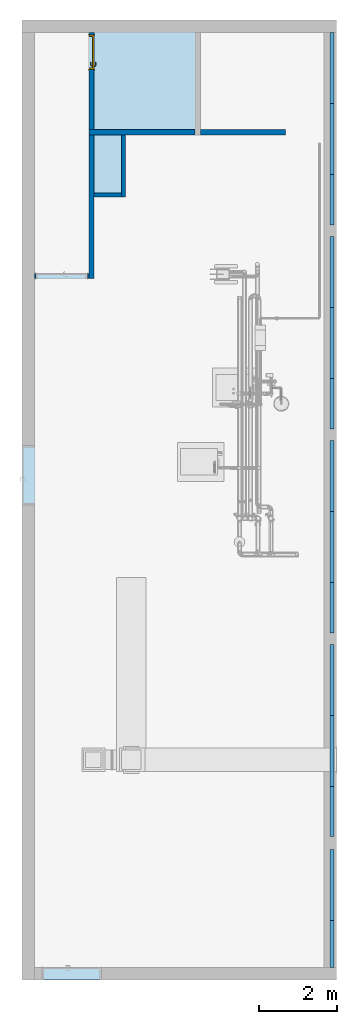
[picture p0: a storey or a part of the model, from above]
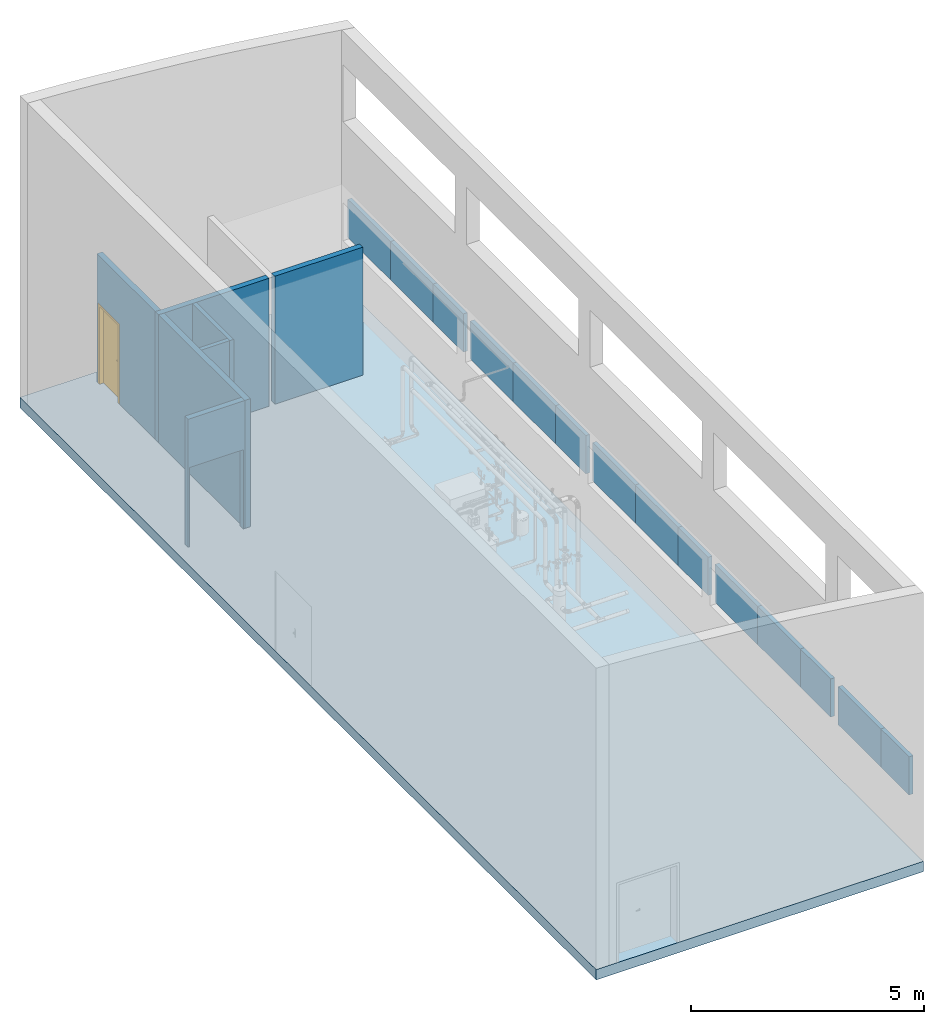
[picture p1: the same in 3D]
Properties of the parts of a building model (IFC2X3), part 1 of 2

# File
Description: ViewDefinition [CoordinationView_V2.0]
File name: 0001
Time: 2023-12-08T14:06:30+01:00
Written by: ODA SDAI 22.12
Made in: 23.0.11.19 - Exporter 23.0.11.19 - Interface utilisateur alternative 23.0.11.19

# IfcProject, 0001
LongName: Nom du projet; Phase: Etat du projet

# IfcSite, Default
RefLatitude: 48, 51, 23, 807373; RefLongitude: 2, 21, 7, 999076; RefElevation: 0 mm

# IfcBuilding
Pset_BuildingCommon - NumberOfStoreys: 3

# IfcBuildingStorey: Niveau:Pointe 8 mm (3)
Name | LongName | Elevation (mm)
Niveau 0 | Niveau 0 | 270
Niveau 1 | Niveau 1 | 3880
Niveau 2 | Niveau 2 | 8105

# IfcBuildingElementProxy: CTA YORK:CTA YORK, CTA YORK:CTA YORK:757549
In: Niveau 0
Type - Material: <Unnamed> (4)
Pset_BuildingElementProxyCommon - Reference: CTA YORK; sets with these values: 2
Pset_ProvisionForVoid - Width: 5000 mm; Height: 750 mm; Depth: 730 mm
Group: Génie climatique Soufflage 1; Génie climatique Air Neuf 1; Génie climatique Reprise 2

# IfcBuildingElementProxy: Chaudière Weishaupt WTC-GB 120-A:Chaudière Weishaupt WTC-GB 120-A (2)
In: Niveau 0
Type - Material: <Unnamed>, Panneau métallique gris foncé, Panneau métallique blanc, logo
Pset_BuildingElementProxyCommon - Reference: Chaudière Weishaupt WTC-GB 120-A; sets with these values: 2
Name (Chaudière Weishaupt WTC-GB 120-A:Chaudière Weishaupt WTC-GB 120-A:...) | Group
1231440 | Chauffage retour 4; Chauffage retour primaire 2; Chauffage aller primaire 4; gaz naturel 5
1236392 | Chauffage retour primaire 2; Chauffage aller primaire 4

# IfcBuildingElementProxy: Clapet coupe-feu - Rectangulaire - Simple:Standard (2)
In: Niveau 1
Type - Material: <Unnamed>
Pset_BuildingElementProxyCommon - Reference: Standard; sets with these values: 2
Pset_ProvisionForVoid - Width: 150 mm; Height: 424 mm; Depth: 424 mm
Name (Clapet coupe-feu - Rectangulaire - Simple:Standard:...) | Group
756469 | Génie climatique Soufflage 1
758548 | Génie climatique Reprise 2

# IfcBuildingElementProxy: Ecran clavier souris PC:Ecran clavier souris PC (21)
In: Niveau 1
Type - Material: Plastique - Blanc brillant (122), <Unnamed>, Verre - Noir brillant
Pset_BuildingElementProxyCommon - Reference: Ecran clavier souris PC; sets with these values: 2
Name (Ecran clavier souris PC:Ecran clavier souris PC:...) | Material
1175628
1175630 | Plastique - Blanc brillant, <Unnamed>, Verre - Noir brillant
1175632 | Plastique - Blanc brillant, <Unnamed>, Verre - Noir brillant
1175634 | Plastique - Blanc brillant, <Unnamed>, Verre - Noir brillant
1175636 | Plastique - Blanc brillant, <Unnamed>, Verre - Noir brillant
1175638 | Plastique - Blanc brillant, <Unnamed>, Verre - Noir brillant
1175640 | Plastique - Blanc brillant, <Unnamed>, Verre - Noir brillant
1175642 | Plastique - Blanc brillant, <Unnamed>, Verre - Noir brillant
1175654 | Plastique - Blanc brillant, <Unnamed>, Verre - Noir brillant
1175657 | Plastique - Blanc brillant, <Unnamed>, Verre - Noir brillant
1175659 | Plastique - Blanc brillant, <Unnamed>, Verre - Noir brillant
1175664 | Plastique - Blanc brillant, <Unnamed>, Verre - Noir brillant
1175665 | Plastique - Blanc brillant, <Unnamed>, Verre - Noir brillant
1175669 | Plastique - Blanc brillant, <Unnamed>, Verre - Noir brillant
1175670 | Plastique - Blanc brillant, <Unnamed>, Verre - Noir brillant
1175674 | Plastique - Blanc brillant, <Unnamed>, Verre - Noir brillant
1175675 | Plastique - Blanc brillant, <Unnamed>, Verre - Noir brillant
1175679 | Plastique - Blanc brillant, <Unnamed>, Verre - Noir brillant
1175680 | Plastique - Blanc brillant, <Unnamed>, Verre - Noir brillant
1175684 | Plastique - Blanc brillant, <Unnamed>, Verre - Noir brillant
1175685 | Plastique - Blanc brillant, <Unnamed>, Verre - Noir brillant

# IfcBuildingElementProxy: HC_Expansion Vessel_MEPcontent_Flamco_26105 Contraflex100 25-6:vase d'expansion gitral, HC_Expansion Vessel_MEPcontent_Flamco_26105 Contraflex100 25-6:vase d'expansion gitral:1371709
In: Niveau 0
Type - Material: Color RGB 204-0-0
Type - Pset_ManufacturerTypeInformation - Manufacturer: Flamco
Pset_BuildingElementProxyCommon - Reference: vase d'expansion gitral; sets with these values: 2

# IfcBuildingElementProxy: Imprimante - Table:Imprimante - Table, Imprimante - Table:Imprimante - Table:1175661
In: Niveau 1
Type - Material: Plastique - Blanc cassé (5)
Pset_BuildingElementProxyCommon - Reference: Imprimante - Table; sets with these values: 2

# IfcBuildingElementProxy: M_Heat Exchanger_Plate_MEPcontent_CHAROT_Solo_L_FR-FR:THIS IS A TYPE CATALOG FAMILY, M_Heat Exchanger_Plate_MEPcontent_CHAROT_Solo_L_FR-FR:THIS IS A TYPE CATALOG FAMILY:1247341
In: Niveau 0
Type - Material: Color RGB 226-110-014, Color RGB 191-191-191, Color RGB 103-103-103, Color RGB 252-188-132
Type - Pset_ManufacturerTypeInformation - Manufacturer: CHAROT
Type - Pset_ProvisionForVoid - Width: 506 mm; Height: 995 mm; Diameter: 63.5 mm; Depth: 710 mm
Material: Color RGB 191-191-191, Color RGB 252-188-132, Color RGB 226-110-014, Color RGB 103-103-103; Group: Chauffage retour 3
Pset_BuildingElementProxyCommon - Reference: THIS IS A TYPE CATALOG FAMILY; sets with these values: 2
Pset_ProvisionForVoid - Width: 0.154229 mm

# IfcBuildingElementProxy: M_Meter_Gas_MEPcontent_Unspecified:G2.5, M_Meter_Gas_MEPcontent_Unspecified:G2.5:1422788
In: Niveau 0
Type - Material: Color RGB 255-255-0 (2), Color RGB 127-127-127 (2), Color RGB 255-255-255 (2)
Type - Pset_ManufacturerTypeInformation - Manufacturer: Unspecified
Type - Pset_ProvisionForVoid - Width: 133 mm
Pset_BuildingElementProxyCommon - Reference: G2.5; sets with these values: 2
Pset_ProvisionForVoid - Width: 0.0405384 mm
Group: gaz naturel 5

# IfcBuildingElementProxy: Male:Male (221)
In: Niveau 0
Type - Material: Copper Conex
Pset_BuildingElementProxyCommon - Reference: Male; sets with these values: 2
Name (Male:Male:...)
1362084
1362085
1362086
1362087
1362088
1362089
1362090
1362091
1362092
1362093
1362094
1362095
1362096
1362097
1362098
1362099
1362100
1362101
1362102
1362103
1362104
1362105
1362106
1362107
1362711
1362712
1362713
1362714
1362715
1362716
1362717
1362718
1362719
1362720
1362721
1362722
1362723
1362724
1362725
1362726
1362727
1362728
1362729
1362730
1362731
1362732
1362733
1362734
1362820
1362821
1362822
1362823
1362824
1362825
1362826
1362827
1362828
1362829
1362830
1362831
1362832
1362833
1362834
1362835
1362836
1362837
1362838
1362839
1362840
1362841
1362842
1362843
1363901
1363902
1363903
1363904
1363905
1363906
1363907
1363908
1363909
1363910
1363911
1363912
1363913
1363914
1363915
1363916
1363917
1363918
1363919
1363920
1363921
1363922
1363923
1363924
1364621
1364622
1364623
1364624
1364625
1364626
1364627
1364628
1364629
1364630
1364631
1364632
1364633
1364634
1364635
1364636
1364637
1364638
1364639
1364640
1364641
1364642
1364643
1364644
1364876
1364877
1364878
1364879
1364880
1364881
1364882
1364883
1364884
1364885
1364886
1364887
1364888
1364889
1364890
1364891
1364892
1364893
1364894
1364895
1364896
1364897
1364898
1364899
1364900
1364901
1364902
1364903
1364974
1364975
1364976
1364977
1364978
1364979
1364980
1364981
1364982
1364983
1364984
1364985
1364986
1364987
1364988
1364989
1364990
1364991
1364992
1364993
1364994
1364995
1364996
1364997
1364998
1364999
1365000
1365001
1365287
1365288
1365289
1365290
1365291
1365292
1365293
1365294
1365295
1365296
1365297
1365298
1365299
1365300
1365301
1365302
1365303
1365304
1365305
1365306
1365307
1365308
1365309
1365310
1365311
1365312
1365313
1365314
1383095
1383096
1383097
1383098
1383099
1383100
1383101
1383215
1383372
1400765
1400766
1400767
1400768
1400769
1400770
1400771
1400772

# IfcBuildingElementProxy: Plumbing_Other_IVAR_DirtstopXL_Swiveling-Magnetic-Dirt-Separator-With-Strainer:- Pot à boues Flamco-Clean Smart 1''1/4 33 x 42 Ecoplus, Plumbing_Other_IVAR_DirtstopXL_Swiveling-Magnetic-Dirt-Separator-With-Strainer:- Pot à boues Flamco-Clean Smart 1''1/4 33 x 42 Ecoplus:1433220
In: Niveau 0
Type - Material: <Unnamed> (2), BRASS - CW617N (9), Techno-Polymer RAL7016 (12), Techno-Polymer BLACK (4), PA Nylon 6 - White, Brass - Nickel, EPDM - Black (2)
Type - Pset_ManufacturerTypeInformation - Manufacturer: IVAR
Pset_BuildingElementProxyCommon - Reference: - Pot à boues Flamco-Clean Smart 1''1/4 33 x 42 Ecoplus; sets with these values: 2

# IfcBuildingElementProxy: Poste de travail PC:Poste de travail PC (21)
In: Niveau 1
Type - Material: Plastique - Noir satiné, Métal - Aluminium satiné
Pset_BuildingElementProxyCommon - Reference: Poste de travail PC; sets with these values: 2
Name (Poste de travail PC:Poste de travail PC:...)
1175627
1175629
1175631
1175633
1175635
1175637
1175639
1175641
1175653
1175656
1175658
1175663
1175666
1175668
1175671
1175673
1175676
1175678
1175681
1175683
1175686

# IfcBuildingElementProxy: Pump-Inline_Circulator-Grundfos_MAGNA3D-EMCS V3-0:MAGNA 32-100 180, Pump-Inline_Circulator-Grundfos_MAGNA3D-EMCS V3-0:MAGNA 32-100 180:1353054
In: Niveau 0
Type - Material: Grundfos - Light Black (7), Grundfos - Red (2), Grundfos - Insulation
Type - Pset_ManufacturerTypeInformation - Manufacturer: Grundfos
Pset_BuildingElementProxyCommon - Reference: MAGNA 32-100 180; sets with these values: 2
Group: Chauffage retour primaire 1

# IfcBuildingElementProxy: Pump-Inline_Circulator-Grundfos_UUPS100:PLEASE USE TYPE CATALOG, Pump-Inline_Circulator-Grundfos_UUPS100:PLEASE USE TYPE CATALOG:1298291
In: Niveau 0
Type - Material: Grundfos - Light Black (2), Grundfos - Red (9)
Type - Pset_ManufacturerTypeInformation - Manufacturer: Grundfos
Pset_BuildingElementProxyCommon - Reference: PLEASE USE TYPE CATALOG; sets with these values: 2
Group: Chauffage aller 5

# IfcBuildingElementProxy: Socle chaudière 1000x1200x200:Socle chaudière 1000x1200x200 (2)
In: Niveau 0
Type - Material: Acier noir, Acier rouge
Pset_BuildingElementProxyCommon - Reference: Socle chaudière 1000x1200x200; sets with these values: 2
Name (Socle chaudière 1000x1200x200:Socle chaudière 1000x1200x200:...)
1224524
1236048

# IfcBuildingElementProxy: Vidéoprojecteur fixé au plafond:Vidéoprojecteur fixé au plafond, Vidéoprojecteur fixé au plafond:Vidéoprojecteur fixé au plafond:981224
In: Niveau 1
Type - Material: Plastique - Noir satiné
Material: Plastique - Noir satiné, Plastique - Blanc brillant, <Unnamed>, Verre - Objectif
Pset_BuildingElementProxyCommon - Reference: Vidéoprojecteur fixé au plafond; sets with these values: 2

# IfcBuildingElementProxy: détendeur gaz:détendeur gaz, détendeur gaz:détendeur gaz:1431917
In: Niveau 0
Type - Material: Par défaut (5)
Type - Pset_ManufacturerTypeInformation - Manufacturer: Mesura
Pset_BuildingElementProxyCommon - Reference: détendeur gaz; sets with these values: 2
Pset_ProvisionForVoid - Depth: 120 mm

# IfcCovering: Plafond composé:Quadrillage 600 x 600 mm (7)
Type - PredefinedType: CEILING
Type - Pset_CoveringCommon - TotalThickness: 52 mm
Material: Par défaut 36 mm, Panneau de plafond 600 x 600 16 mm
Pset_CoveringCommon - Reference: Quadrillage 600 x 600 mm; Finish: Panneau de plafond 600 x 600;
Pset_QuantityTakeOff - Reference: Quadrillage 600 x 600 mm
Name (Plafond composé:Quadrillage 600 x 600 mm:...) | In
737611 | Niveau 0
737628 | Niveau 0
737641 | Niveau 1
737655 | Niveau 1
737665 | Niveau 1
737673 | Niveau 1
737682 | Niveau 1

# IfcCurtainWall: Mur-rideau:Vitrage extérieur (10)
Type - Pset_CurtainWallCommon - IsExternal: yes
Pset_CurtainWallCommon - Reference: Vitrage extérieur
Pset_QuantityTakeOff - Reference: Vitrage extérieur
Name (Mur-rideau:Vitrage extérieur:...) | In
739993 | Niveau 0
740630 | Niveau 0
740654 | Niveau 0
740678 | Niveau 0
740854 | Niveau 0
741319 | Niveau 1
741387 | Niveau 1
741411 | Niveau 1
741435 | Niveau 1
741660 | Niveau 1

# IfcDistributionPort (717)
Description: Flow
Name | FlowDirection | Group
InPort_750789 | SINK | Génie climatique Soufflage 1
OutPort_755056 | SOURCE | Génie climatique Soufflage 1
InPort_750978 | SINK | Génie climatique Soufflage 1
OutPort_750789 | SOURCE | Génie climatique Soufflage 1
InPort_750800 | SINK | Génie climatique Soufflage 1
2 x OutPort_750978 | SOURCE | Génie climatique Soufflage 1
InPort_750837 | SINK | Génie climatique Soufflage 1
OutPort_750800 | SOURCE | Génie climatique Soufflage 1
InPort_750882 | SINK | Génie climatique Soufflage 1
2 x OutPort_750817 | SOURCE | Génie climatique Soufflage 1
InPort_752768 | SINK | Génie climatique Soufflage 1
InPort_750817 | SINK | Génie climatique Soufflage 1
OutPort_750837 | SOURCE | Génie climatique Soufflage 1
InPort_752774 | SINK | Génie climatique Soufflage 1
2 x OutPort_750841 | SOURCE | Génie climatique Soufflage 1
InPort_750918 | SINK | Génie climatique Soufflage 1
InPort_750841 | SINK | Génie climatique Soufflage 1
OutPort_750882 | SOURCE | Génie climatique Soufflage 1
InPort_752785 | SINK | Génie climatique Soufflage 1
2 x OutPort_750885 | SOURCE | Génie climatique Soufflage 1
InPort_750949 | SINK | Génie climatique Soufflage 1
InPort_750885 | SINK | Génie climatique Soufflage 1
OutPort_750918 | SOURCE | Génie climatique Soufflage 1
InPort_750921 | SINK | Génie climatique Soufflage 1
OutPort_750949 | SOURCE | Génie climatique Soufflage 1
InPort_750958 | SINK | Génie climatique Soufflage 1
OutPort_750921 | SOURCE | Génie climatique Soufflage 1
InPort_750952 | SINK | Génie climatique Soufflage 1
OutPort_750958 | SOURCE | Génie climatique Soufflage 1
InPort_752788 | SINK | Génie climatique Soufflage 1
OutPort_750952 | SOURCE | Génie climatique Soufflage 1
InPort_753398 | SINK | Génie climatique Soufflage 1
InPort_752171 | SINK | Génie climatique Soufflage 1
OutPort_752765 | SOURCE | Génie climatique Soufflage 1
InPort_752287 | SINK | Génie climatique Soufflage 1
OutPort_752771 | SOURCE | Génie climatique Soufflage 1
InPort_752402 | SINK | Génie climatique Soufflage 1
OutPort_752782 | SOURCE | Génie climatique Soufflage 1
InPort_752454 | SINK | Génie climatique Soufflage 1
OutPort_752788 | SOURCE | Génie climatique Soufflage 1
InPort_752765 | SINK | Génie climatique Soufflage 1
OutPort_752768 | SOURCE | Génie climatique Soufflage 1
InPort_752771 | SINK | Génie climatique Soufflage 1
OutPort_752774 | SOURCE | Génie climatique Soufflage 1
InPort_752782 | SINK | Génie climatique Soufflage 1
OutPort_752785 | SOURCE | Génie climatique Soufflage 1
InPort_753417 | SINK | Génie climatique Soufflage 1
OutPort_753398 | SOURCE | Génie climatique Soufflage 1
InPort_753420 | SINK | Génie climatique Soufflage 1
OutPort_753417 | SOURCE | Génie climatique Soufflage 1
InPort_753441 | SINK | Génie climatique Soufflage 1
3 x OutPort_753420 | SOURCE | Génie climatique Soufflage 1
InPort_754116 | SINK | Génie climatique Soufflage 1
InPort_754103 | SINK | Génie climatique Soufflage 1
InPort_753433 | SINK | Génie climatique Soufflage 1
2 x OutPort_753475 | SOURCE | Génie climatique Soufflage 1
InPort_753454 | SINK | Génie climatique Soufflage 1
OutPort_753433 | SOURCE | Génie climatique Soufflage 1
InPort_753476 | SINK | Génie climatique Soufflage 1
OutPort_753441 | SOURCE | Génie climatique Soufflage 1
InPort_753444 | SINK | Génie climatique Soufflage 1
OutPort_753454 | SOURCE | Génie climatique Soufflage 1
InPort_754094 | SINK | Génie climatique Soufflage 1
OutPort_753444 | SOURCE | Génie climatique Soufflage 1
InPort_753481 | SINK | Génie climatique Soufflage 1
InPort_753475 | SINK | Génie climatique Soufflage 1
2 x OutPort_753476 | SOURCE | Génie climatique Soufflage 1
InPort_754090 | SINK | Génie climatique Soufflage 1
InPort_754097 | SINK | Génie climatique Soufflage 1
OutPort_753481 | SOURCE | Génie climatique Soufflage 1
InPort_753735 | SINK | Génie climatique Soufflage 1
OutPort_754113 | SOURCE | Génie climatique Soufflage 1
InPort_753793 | SINK | Génie climatique Soufflage 1
OutPort_754100 | SOURCE | Génie climatique Soufflage 1
InPort_753835 | SINK | Génie climatique Soufflage 1
OutPort_754087 | SOURCE | Génie climatique Soufflage 1
InPort_753912 | SINK | Génie climatique Soufflage 1
OutPort_754097 | SOURCE | Génie climatique Soufflage 1
InPort_753971 | SINK | Génie climatique Soufflage 1
OutPort_754094 | SOURCE | Génie climatique Soufflage 1
InPort_754087 | SINK | Génie climatique Soufflage 1
OutPort_754090 | SOURCE | Génie climatique Soufflage 1
InPort_754100 | SINK | Génie climatique Soufflage 1
OutPort_754103 | SOURCE | Génie climatique Soufflage 1
InPort_754113 | SINK | Génie climatique Soufflage 1
OutPort_754116 | SOURCE | Génie climatique Soufflage 1
InPort_755056 | SINK | Génie climatique Soufflage 1
OutPort_755057 | SOURCE | Génie climatique Soufflage 1
InPort_755057 | SINK | Génie climatique Soufflage 1
OutPort_755218 | SOURCE | Génie climatique Soufflage 1
InPort_755218 | SINK | Génie climatique Soufflage 1
OutPort_756472 | SOURCE | Génie climatique Soufflage 1
InPort_756469 | SINK | Génie climatique Soufflage 1
OutPort_755245 | SOURCE | Génie climatique Soufflage 1
InPort_755245 | SINK | Génie climatique Soufflage 1
OutPort_755273 | SOURCE | Génie climatique Soufflage 1
InPort_755273 | SINK | Génie climatique Soufflage 1
OutPort_755256 | SOURCE | Génie climatique Soufflage 1
InPort_755256 | SINK | Génie climatique Soufflage 1
OutPort_757967 | SOURCE | Génie climatique Soufflage 1
InPort_757967 | SINK | Génie climatique Soufflage 1
OutPort_755277 | SOURCE | Génie climatique Soufflage 1
InPort_755277 | SINK | Génie climatique Soufflage 1
OutPort_757968 | SOURCE | Génie climatique Soufflage 1
InPort_756472 | SINK | Génie climatique Soufflage 1
OutPort_756469 | SOURCE | Génie climatique Soufflage 1
InPort_757968 | SINK | Génie climatique Soufflage 1
OutPort_757549 | SOURCE | Génie climatique Soufflage 1
InPort_757549 | SINK | Génie climatique Air Neuf 1
OutPort_763756 | SOURCE | Génie climatique Air Neuf 1
InPort_757549 | SINK | Génie climatique Reprise 2
OutPort_758402 | SOURCE | Génie climatique Reprise 2
InPort_758050 | SINK | Génie climatique Reprise 2
OutPort_758134 | SOURCE | Génie climatique Reprise 2
InPort_758504 | SINK | Génie climatique Reprise 2
OutPort_758050 | SOURCE | Génie climatique Reprise 2
InPort_758130 | SINK | Génie climatique Reprise 2
OutPort_758548 | SOURCE | Génie climatique Reprise 2
InPort_758134 | SINK | Génie climatique Reprise 2
OutPort_758130 | SOURCE | Génie climatique Reprise 2
InPort_758402 | SINK | Génie climatique Reprise 2
OutPort_758431 | SOURCE | Génie climatique Reprise 2
InPort_758431 | SINK | Génie climatique Reprise 2
OutPort_758424 | SOURCE | Génie climatique Reprise 2
InPort_758424 | SINK | Génie climatique Reprise 2
OutPort_758506 | SOURCE | Génie climatique Reprise 2
InPort_758483 | SINK | Génie climatique Reprise 2
OutPort_758504 | SOURCE | Génie climatique Reprise 2
InPort_758506 | SINK | Génie climatique Reprise 2
OutPort_758483 | SOURCE | Génie climatique Reprise 2
Port_758548 | SINK | Génie climatique Reprise 2
Port_762252 | SOURCE
Port_762397 | SOURCE
InPort_763721 | SINK | Génie climatique Air Neuf 1
OutPort_763887 | SOURCE | Génie climatique Air Neuf 1
InPort_764588 | SINK | Génie climatique Air Neuf 1
OutPort_763721 | SOURCE | Génie climatique Air Neuf 1
InPort_763756 | SINK | Génie climatique Air Neuf 1
OutPort_764589 | SOURCE | Génie climatique Air Neuf 1
InPort_764589 | SINK | Génie climatique Air Neuf 1
OutPort_764588 | SOURCE | Génie climatique Air Neuf 1
2 x InPort_1226026 | SOURCEANDSINK | Chauffage aller 1
OutPort_1226088 | SOURCEANDSINK | Chauffage aller 1
OutPort_1226085 | SOURCEANDSINK | Chauffage aller 1
InPort_1226918 | SOURCEANDSINK | Chauffage retour 3
2 x OutPort_1227515 | SOURCEANDSINK | Chauffage retour 3
2 x InPort_1227406 | SOURCEANDSINK | Chauffage retour 3
2 x OutPort_1227514 | SOURCEANDSINK | Chauffage retour 3
OutPort_1229989 | SOURCEANDSINK | Chauffage retour 3
2 x InPort_1227422 | SOURCEANDSINK | Chauffage retour 3
OutPort_1230780 | SOURCEANDSINK | Chauffage retour 3
InPort_1227514 | SOURCEANDSINK | Chauffage retour 3
2 x InPort_1228611 | SOURCEANDSINK | Chauffage aller 3
2 x OutPort_1231071 | SOURCEANDSINK | Chauffage aller 3
2 x OutPort_1231069 | SOURCEANDSINK | Chauffage aller 3
3 x InPort_1228619 | SOURCEANDSINK | Chauffage aller 3
2 x OutPort_1247731 | SOURCEANDSINK | Chauffage aller 3
2 x OutPort_1301528 | SOURCEANDSINK | Chauffage aller 3
InPort_1229948 | SOURCEANDSINK | Chauffage aller 4
OutPort_1229989 | SOURCEANDSINK | Chauffage aller 4
Port_1229948 | SOURCEANDSINK | Chauffage aller 4
2 x InPort_1230697 | SOURCEANDSINK | Chauffage aller 3
2 x OutPort_1231029 | SOURCEANDSINK | Chauffage aller 3
OutPort_1276218 | SOURCEANDSINK | Chauffage aller 3
InPort_1230780 | SOURCEANDSINK | Chauffage retour 3
OutPort_1276214 | SOURCEANDSINK | Chauffage retour 3
2 x InPort_1231015 | SOURCEANDSINK | Chauffage aller 3
InPort_1231440 | SOURCEANDSINK | Chauffage retour 4
2 x OutPort_1251086 | SOURCEANDSINK | Chauffage retour 4
InPort_1231440 | SOURCEANDSINK | Chauffage retour primaire 2
OutPort_1318675 | SOURCEANDSINK | Chauffage retour primaire 2
Port_1231440 | SINK
InPort_1231440 | SOURCEANDSINK | Chauffage aller primaire 4
OutPort_1319182 | SOURCEANDSINK | Chauffage aller primaire 4
Port_1231440 | SOURCE
InPort_1231440 | SINK | gaz naturel 5
OutPort_1422933 | SOURCE | gaz naturel 5
2 x InPort_1232776 | SOURCEANDSINK | Chauffage aller 3
2 x OutPort_1247733 | SOURCEANDSINK | Chauffage aller 3
InPort_1232794 | SOURCEANDSINK | Chauffage aller 5
OutPort_1233212 | SOURCEANDSINK | Chauffage aller 5
Port_1232794 | SOURCEANDSINK | Chauffage aller 5
2 x InPort_1232892 | SOURCEANDSINK | Chauffage aller 5
OutPort_1233118 | SOURCEANDSINK | Chauffage aller 5
2 x OutPort_1233286 | SOURCEANDSINK | Chauffage aller 5
InPort_1233212 | SOURCEANDSINK | Chauffage aller 5
2 x OutPort_1233287 | SOURCEANDSINK | Chauffage aller 5
2 x InPort_1233215 | SOURCEANDSINK | Chauffage aller 5
OutPort_1233302 | SOURCEANDSINK | Chauffage aller 5
InPort_1233286 | SOURCEANDSINK | Chauffage aller 5
2 x InPort_1233291 | SOURCEANDSINK | Chauffage aller 5
2 x OutPort_1298984 | SOURCEANDSINK | Chauffage aller 5
2 x OutPort_1301420 | SOURCEANDSINK | Chauffage aller 5
InPort_1233302 | SOURCEANDSINK | Chauffage aller 5
OutPort_1276068 | SOURCEANDSINK | Chauffage aller 5
2 x InPort_1233352 | SOURCEANDSINK | Chauffage aller 5
2 x OutPort_1301418 | SOURCEANDSINK | Chauffage aller 5
3 x InPort_1233375 | SOURCEANDSINK | Chauffage aller 5
2 x OutPort_1300699 | SOURCEANDSINK | Chauffage aller 5
2 x OutPort_1233546 | SOURCEANDSINK | Chauffage aller 5
2 x InPort_1233538 | SOURCEANDSINK | Chauffage aller 5
2 x OutPort_1247588 | SOURCEANDSINK | Chauffage aller 5
Port_1233709 | SOURCEANDSINK | Chauffage retour primaire 2
InPort_1233709 | SOURCEANDSINK | Chauffage retour primaire 2
2 x OutPort_1233780 | SOURCEANDSINK | Chauffage retour primaire 2
2 x InPort_1233772 | SOURCEANDSINK | Chauffage retour primaire 2
OutPort_1234849 | SOURCEANDSINK | Chauffage retour primaire 2
2 x InPort_1233937 | SOURCEANDSINK | Chauffage retour primaire 2
OutPort_1276390 | SOURCEANDSINK | Chauffage retour primaire 2
OutPort_1234851 | SOURCEANDSINK | Chauffage retour primaire 2
InPort_1234127 | SOURCEANDSINK | Chauffage aller 2
2 x OutPort_1300229 | SOURCEANDSINK | Chauffage aller 2
2 x InPort_1234127 | SOURCEANDSINK | Chauffage retour primaire 1
2 x OutPort_1235545 | SOURCEANDSINK | Chauffage retour primaire 1
OutPort_1234851 | SOURCEANDSINK | Chauffage retour primaire 1
2 x InPort_1234299 | SOURCEANDSINK | Chauffage retour primaire 1
2 x OutPort_1235543 | SOURCEANDSINK | Chauffage retour primaire 1
2 x InPort_1234299 | SOURCEANDSINK | Chauffage retour primaire 2
2 x OutPort_1238957 | SOURCEANDSINK | Chauffage retour primaire 2
OutPort_1234350 | SOURCEANDSINK | Chauffage retour primaire 2
2 x OutPort_1238229 | SOURCEANDSINK | Chauffage retour primaire 1
InPort_1234849 | SOURCEANDSINK | Chauffage retour primaire 2
OutPort_1276386 | SOURCEANDSINK | Chauffage retour primaire 2
2 x InPort_1235533 | SOURCEANDSINK | Chauffage retour primaire 1
InPort_1235629 | SOURCEANDSINK | Chauffage aller primaire 4
2 x OutPort_1262224 | SOURCEANDSINK | Chauffage aller primaire 4
Port_1235629 | SOURCEANDSINK | Chauffage aller primaire 4
2 x InPort_1235760 | SOURCEANDSINK | Chauffage aller primaire 4
2 x OutPort_1262222 | SOURCEANDSINK | Chauffage aller primaire 4
3 x InPort_1235770 | SOURCEANDSINK | Chauffage aller primaire 4
2 x OutPort_1300048 | SOURCEANDSINK | Chauffage aller primaire 4
2 x OutPort_1239954 | SOURCEANDSINK | Chauffage aller primaire 4
Port_1235770 | SOURCEANDSINK | Chauffage aller primaire 4
Port_1235854 | SOURCEANDSINK | Chauffage aller primaire 1
InPort_1236392 | SOURCEANDSINK | Chauffage aller primaire 4
OutPort_1238980 | SOURCEANDSINK | Chauffage aller primaire 4
2 x Port_1236392 | SINK
InPort_1236392 | SOURCEANDSINK | Chauffage retour primaire 2
OutPort_1238888 | SOURCEANDSINK | Chauffage retour primaire 2
2 x Port_1236392 | SOURCE
2 x Port_1237930 | SOURCEANDSINK | Chauffage aller 6
2 x InPort_1237938 | SOURCEANDSINK | Chauffage retour primaire 1
2 x OutPort_1238240 | SOURCEANDSINK | Chauffage retour primaire 1
2 x InPort_1238232 | SOURCEANDSINK | Chauffage retour primaire 1
OutPort_1238373 | SOURCEANDSINK | Chauffage retour primaire 1
2 x InPort_1238361 | SOURCEANDSINK | Chauffage retour primaire 1
2 x OutPort_1318694 | SOURCEANDSINK | Chauffage retour primaire 1
OutPort_1310541 | SOURCEANDSINK | Chauffage retour primaire 1
InPort_1238373 | SOURCEANDSINK | Chauffage retour primaire 1
OutPort_1366838 | SOURCEANDSINK | Chauffage retour primaire 1
2 x InPort_1238876 | SOURCEANDSINK | Chauffage retour primaire 2
2 x OutPort_1238960 | SOURCEANDSINK | Chauffage retour primaire 2
2 x OutPort_1238890 | SOURCEANDSINK | Chauffage retour primaire 2
InPort_1238888 | SOURCEANDSINK | Chauffage retour primaire 2
2 x InPort_1238893 | SOURCEANDSINK | Chauffage retour primaire 2
InPort_1238980 | SOURCEANDSINK | Chauffage aller primaire 4
2 x OutPort_1239957 | SOURCEANDSINK | Chauffage aller primaire 4
2 x InPort_1238994 | SOURCEANDSINK | Chauffage aller primaire 4
Port_1240949 | SOURCE
2 x Port_1241064 | SOURCEANDSINK | Chauffage aller primaire 3
2 x Port_1247341 | SOURCE
InPort_1247341 | SOURCEANDSINK | Chauffage retour 3
OutPort_1247673 | SOURCEANDSINK | Chauffage retour 3
Port_1247341 | SINK
InPort_1247532 | SOURCEANDSINK | Chauffage retour 2
OutPort_1247586 | SOURCEANDSINK | Chauffage retour 2
Port_1247532 | SOURCEANDSINK | Chauffage retour 2
InPort_1247586 | SOURCEANDSINK | Chauffage aller 5
2 x InPort_1247649 | SOURCEANDSINK | Chauffage aller 3
OutPort_1247673 | SOURCEANDSINK | Chauffage aller 3
OutPort_1247724 | SOURCEANDSINK | Chauffage aller 3
2 x InPort_1247722 | SOURCEANDSINK | Chauffage aller 3
2 x OutPort_1247726 | SOURCEANDSINK | Chauffage aller 3
InPort_1247724 | SOURCEANDSINK | Chauffage aller 3
Port_1247777 | SOURCEANDSINK | Chauffage retour 1
InPort_1247777 | SOURCEANDSINK | Chauffage retour 1
2 x OutPort_1248059 | SOURCEANDSINK | Chauffage retour 1
4 x InPort_1247800 | SOURCEANDSINK | Chauffage retour 1
2 x OutPort_1248134 | SOURCEANDSINK | Chauffage retour 1
2 x OutPort_1248155 | SOURCEANDSINK | Chauffage retour 1
2 x OutPort_1248173 | SOURCEANDSINK | Chauffage retour 1
InPort_1248126 | SOURCEANDSINK | Chauffage retour 1
Port_1248126 | SOURCEANDSINK | Chauffage retour 1
InPort_1248144 | SOURCEANDSINK | Chauffage retour 1
Port_1248144 | SOURCEANDSINK | Chauffage retour 1
InPort_1248165 | SOURCEANDSINK | Chauffage retour 1
Port_1248165 | SOURCEANDSINK | Chauffage retour 1
Port_1248396 | SOURCE
Port_1248396 | SINK
Port_1249217 | SOURCE
Port_1250934 | SINK
Port_1251073 | SOURCEANDSINK | Chauffage retour 4
InPort_1251073 | SOURCEANDSINK | Chauffage retour 4
2 x InPort_1251114 | SOURCEANDSINK | Chauffage retour 5
2 x OutPort_1251134 | SOURCEANDSINK | Chauffage retour 5
2 x OutPort_1251160 | SOURCEANDSINK | Chauffage retour 5
InPort_1251122 | SOURCEANDSINK | Chauffage retour 5
Port_1251122 | SOURCEANDSINK | Chauffage retour 5
InPort_1251152 | SOURCEANDSINK | Chauffage retour 5
Port_1251152 | SOURCEANDSINK | Chauffage retour 5
2 x Port_1251172 | SOURCEANDSINK | Chauffage retour 5
Port_1251988 | SINK
2 x Port_1252877 | SOURCEANDSINK
Port_1253088 | SOURCE
Port_1253587 | SINK
Port_1253587 | SOURCE
Port_1272783 | SOURCEANDSINK
InPort_1276066 | SOURCEANDSINK | Chauffage aller 5
2 x OutPort_1276070 | SOURCEANDSINK | Chauffage aller 5
Port_1276066 | SOURCEANDSINK
InPort_1276068 | SOURCEANDSINK | Chauffage aller 5
InPort_1276212 | SOURCEANDSINK
OutPort_1276216 | SOURCEANDSINK
InPort_1276212 | SOURCEANDSINK | Chauffage retour 3
OutPort_1276218 | SOURCEANDSINK | Chauffage retour 3
InPort_1276214 | SOURCEANDSINK | Chauffage retour 3
OutPort_1276216 | SOURCEANDSINK | Chauffage retour 3
InPort_1276245 | SOURCEANDSINK
OutPort_1276390 | SOURCEANDSINK
InPort_1276245 | SOURCEANDSINK | Chauffage retour primaire 2
2 x OutPort_1276388 | SOURCEANDSINK | Chauffage retour primaire 2
InPort_1276386 | SOURCEANDSINK | Chauffage retour primaire 2
Port_1298291 | SOURCEANDSINK
Port_1298291 | SOURCEANDSINK | Chauffage aller 5
Port_1298291 | SOURCE
InPort_1298861 | SOURCEANDSINK | Chauffage aller 5
Port_1298861 | SOURCEANDSINK
Port_1299774 | SOURCE
InPort_1299923 | SOURCEANDSINK | Chauffage aller primaire 4
Port_1299923 | SOURCEANDSINK | Chauffage aller primaire 4
Port_1300102 | SOURCEANDSINK | Chauffage aller 2
InPort_1300102 | SOURCEANDSINK | Chauffage aller 2
Port_1300453 | SOURCE
Port_1300605 | SOURCEANDSINK | Chauffage aller 5
InPort_1300605 | SOURCEANDSINK | Chauffage aller 5
Port_1301314 | SOURCE
InPort_1301440 | SOURCEANDSINK | Chauffage aller 3
Port_1301440 | SOURCEANDSINK | Chauffage aller 3
Port_1301603 | SOURCE
InPort_1310541 | SOURCEANDSINK | Chauffage retour primaire 1
OutPort_1310578 | SOURCEANDSINK | Chauffage retour primaire 1
InPort_1310578 | SOURCEANDSINK | Chauffage retour primaire 1
OutPort_1400764 | SOURCEANDSINK | Chauffage retour primaire 1
2 x InPort_1311545 | SOURCEANDSINK | Chauffage aller 6
OutPort_1311698 | SOURCEANDSINK | Chauffage aller 6
OutPort_1311610 | SOURCEANDSINK | Chauffage aller 6
Port_1311610 | SOURCEANDSINK | Chauffage aller 6
Port_1311698 | SOURCEANDSINK | Chauffage aller 6
Port_1317772 | SOURCEANDSINK | Chauffage retour primaire 1
InPort_1317772 | SOURCEANDSINK | Chauffage retour primaire 1
2 x OutPort_1433431 | SOURCEANDSINK | Chauffage retour primaire 1
2 x InPort_1317774 | SOURCEANDSINK | Chauffage retour primaire 1
2 x OutPort_1353099 | SOURCEANDSINK | Chauffage retour primaire 1
3 x InPort_1318660 | SOURCEANDSINK | Chauffage aller 7
OutPort_1318692 | SOURCEANDSINK | Chauffage aller 7
OutPort_1318675 | SOURCEANDSINK | Chauffage aller 7
2 x OutPort_1318892 | SOURCEANDSINK | Chauffage aller 7
2 x InPort_1318690 | SOURCEANDSINK | Chauffage retour primaire 1
OutPort_1318692 | SOURCEANDSINK | Chauffage retour primaire 1
2 x InPort_1318855 | SOURCEANDSINK | Chauffage aller 7
OutPort_1318957 | SOURCEANDSINK | Chauffage aller 7
2 x Port_1318955 | SOURCEANDSINK
Port_1318957 | SOURCEANDSINK | Chauffage aller 7
3 x InPort_1319134 | SOURCEANDSINK | Chauffage aller 9
OutPort_1319207 | SOURCEANDSINK | Chauffage aller 9
2 x OutPort_1320291 | SOURCEANDSINK | Chauffage aller 9
OutPort_1319683 | SOURCEANDSINK | Chauffage aller 9
InPort_1319182 | SOURCEANDSINK | Chauffage aller primaire 4
OutPort_1319685 | SOURCEANDSINK | Chauffage aller primaire 4
2 x InPort_1319199 | SOURCEANDSINK | Chauffage aller 9
2 x OutPort_1366607 | SOURCEANDSINK | Chauffage aller 9
2 x OutPort_1319215 | SOURCEANDSINK | Chauffage aller 9
InPort_1319207 | SOURCEANDSINK | Chauffage aller 9
OutPort_1366602 | SOURCEANDSINK | Chauffage aller 9
2 x InPort_1319209 | SOURCEANDSINK | Chauffage aller 9
2 x OutPort_1319417 | SOURCEANDSINK | Chauffage aller 9
Port_1319377 | SOURCEANDSINK | Chauffage aller 9
InPort_1319377 | SOURCEANDSINK | Chauffage aller 9
InPort_1319683 | SOURCEANDSINK | Chauffage aller 9
OutPort_1319685 | SOURCEANDSINK | Chauffage aller 9
2 x InPort_1319756 | SOURCEANDSINK | Chauffage aller 9
OutPort_1320357 | SOURCEANDSINK | Chauffage aller 9
2 x Port_1320349 | SOURCEANDSINK
Port_1320357 | SOURCEANDSINK | Chauffage aller 9
2 x InPort_1353054 | SOURCEANDSINK | Chauffage retour primaire 1
2 x OutPort_1353096 | SOURCEANDSINK | Chauffage retour primaire 1
Port_1353054 | SOURCEANDSINK
2 x InPort_1353094 | SOURCEANDSINK | Chauffage retour primaire 1
OutPort_1353689 | SOURCEANDSINK | Chauffage retour primaire 1
3 x Port_1353682 | SOURCEANDSINK | Chauffage retour primaire 1
2 x InPort_1353684 | SOURCEANDSINK | Chauffage retour primaire 1
OutPort_1353686 | SOURCEANDSINK | Chauffage retour primaire 1
OutPort_1366842 | SOURCEANDSINK | Chauffage retour primaire 1
Port_1353686 | SOURCEANDSINK | Chauffage retour primaire 1
InPort_1353689 | SOURCEANDSINK | Chauffage retour primaire 1
OutPort_1362083 | SOURCEANDSINK | Chauffage retour primaire 1
InPort_1354178 | SOURCEANDSINK | Chauffage aller 8
2 x OutPort_1366078 | SOURCEANDSINK | Chauffage aller 8
Port_1354178 | SOURCEANDSINK | Chauffage aller 8
InPort_1362083 | SOURCEANDSINK | Chauffage retour primaire 1
OutPort_1362710 | SOURCEANDSINK | Chauffage retour primaire 1
InPort_1362710 | SOURCEANDSINK | Chauffage retour primaire 1
OutPort_1362819 | SOURCEANDSINK | Chauffage retour primaire 1
InPort_1362819 | SOURCEANDSINK | Chauffage retour primaire 1
OutPort_1363900 | SOURCEANDSINK | Chauffage retour primaire 1
InPort_1363900 | SOURCEANDSINK | Chauffage retour primaire 1
OutPort_1364620 | SOURCEANDSINK | Chauffage retour primaire 1
InPort_1364620 | SOURCEANDSINK | Chauffage retour primaire 1
OutPort_1364875 | SOURCEANDSINK | Chauffage retour primaire 1
InPort_1364875 | SOURCEANDSINK | Chauffage retour primaire 1
OutPort_1364973 | SOURCEANDSINK | Chauffage retour primaire 1
Port_1364973 | SOURCEANDSINK | Chauffage retour primaire 1
InPort_1365286 | SOURCEANDSINK | Chauffage aller 8
OutPort_1365801 | SOURCEANDSINK | Chauffage aller 8
Port_1365286 | SOURCEANDSINK | Chauffage aller 8
InPort_1365801 | SOURCEANDSINK | Chauffage aller 8
InPort_1366583 | SOURCEANDSINK
OutPort_1366604 | SOURCEANDSINK
InPort_1366583 | SOURCEANDSINK | Chauffage aller 9
InPort_1366602 | SOURCEANDSINK | Chauffage aller 9
OutPort_1366604 | SOURCEANDSINK | Chauffage aller 9
Port_1366793 | SOURCEANDSINK
Port_1366793 | SOURCEANDSINK | Chauffage retour primaire 1
InPort_1366838 | SOURCEANDSINK | Chauffage retour primaire 1
OutPort_1366840 | SOURCEANDSINK | Chauffage retour primaire 1
Port_1366840 | SOURCEANDSINK | Chauffage retour primaire 1
Port_1366842 | SOURCEANDSINK | Chauffage retour primaire 1
Port_1371709 | SINK
Port_1383094 | SOURCEANDSINK | Chauffage aller 10
InPort_1383094 | SOURCEANDSINK | Chauffage aller 10
2 x OutPort_1383820 | SOURCEANDSINK | Chauffage aller 10
InPort_1383509 | SOURCEANDSINK | Chauffage aller 10
2 x OutPort_1383826 | SOURCEANDSINK | Chauffage aller 10
Port_1383509 | SOURCEANDSINK | Chauffage aller 10
2 x InPort_1383810 | SOURCEANDSINK | Chauffage aller 10
2 x OutPort_1383830 | SOURCEANDSINK | Chauffage aller 10
4 x InPort_1383824 | SOURCEANDSINK | Chauffage aller 10
2 x OutPort_1384212 | SOURCEANDSINK | Chauffage aller 10
2 x OutPort_1409150 | SOURCEANDSINK | Chauffage aller 10
Port_1383955 | SOURCEANDSINK | Chauffage aller 10
InPort_1383955 | SOURCEANDSINK | Chauffage aller 10
Port_1384537 | SOURCE
Port_1400764 | SOURCEANDSINK | Chauffage retour primaire 1
2 x Port_1406723 | SOURCEANDSINK
Port_1409053 | SOURCEANDSINK | Chauffage aller 10
InPort_1409053 | SOURCEANDSINK | Chauffage aller 10
OutPort_1409132 | SOURCEANDSINK | Chauffage aller 10
InPort_1409132 | SOURCEANDSINK | Chauffage aller 10
Port_1409182 | SOURCEANDSINK | gaz naturel 1
InPort_1409182 | SOURCEANDSINK | gaz naturel 1
OutPort_1409793 | SOURCEANDSINK | gaz naturel 1
Port_1409265 | SOURCEANDSINK | gaz naturel 1
InPort_1409265 | SOURCEANDSINK | gaz naturel 1
OutPort_1409276 | SOURCEANDSINK | gaz naturel 1
InPort_1409276 | SOURCEANDSINK | gaz naturel 1
OutPort_1409824 | SOURCEANDSINK | gaz naturel 1
2 x InPort_1409643 | SOURCEANDSINK | gaz naturel 2
OutPort_1409667 | SOURCEANDSINK | gaz naturel 2
OutPort_1409669 | SOURCEANDSINK | gaz naturel 2
InPort_1409793 | SOURCEANDSINK | gaz naturel 1
OutPort_1409806 | SOURCEANDSINK | gaz naturel 1
InPort_1409806 | SOURCEANDSINK | gaz naturel 1
OutPort_1409822 | SOURCEANDSINK | gaz naturel 1
2 x InPort_1409812 | SOURCEANDSINK | gaz naturel 1
2 x OutPort_1421416 | SOURCEANDSINK | gaz naturel 1
2 x OutPort_1409838 | SOURCEANDSINK | gaz naturel 1
InPort_1409822 | SOURCEANDSINK | gaz naturel 1
OutPort_1421411 | SOURCEANDSINK | gaz naturel 1
InPort_1409824 | SOURCEANDSINK | gaz naturel 1
2 x InPort_1421369 | SOURCEANDSINK | gaz naturel 1
2 x OutPort_1421413 | SOURCEANDSINK | gaz naturel 1
InPort_1421411 | SOURCEANDSINK | gaz naturel 1
InPort_1421547 | SOURCEANDSINK | gaz naturel 3
OutPort_1421565 | SOURCEANDSINK | gaz naturel 3
Port_1421547 | SOURCEANDSINK | gaz naturel 3
Port_1421557 | SOURCEANDSINK | gaz naturel 3
InPort_1421557 | SOURCEANDSINK | gaz naturel 3
OutPort_1429338 | SOURCEANDSINK | gaz naturel 3
InPort_1421565 | SOURCEANDSINK | gaz naturel 3
OutPort_1429333 | SOURCEANDSINK | gaz naturel 3
InPort_1422788 | SINK | gaz naturel 5
OutPort_1423232 | SOURCE | gaz naturel 5
Port_1422788 | SINK
2 x InPort_1422871 | SOURCEANDSINK | gaz naturel 5
OutPort_1423218 | SOURCEANDSINK | gaz naturel 5
2 x OutPort_1423020 | SOURCEANDSINK | gaz naturel 5
InPort_1422933 | SOURCEANDSINK | gaz naturel 5
OutPort_1423018 | SOURCEANDSINK | gaz naturel 5
InPort_1423018 | SOURCEANDSINK | gaz naturel 5
2 x InPort_1423208 | SOURCEANDSINK | gaz naturel 5
2 x OutPort_1423235 | SOURCEANDSINK | gaz naturel 5
OutPort_1424600 | SOURCEANDSINK | gaz naturel 5
InPort_1423218 | SOURCEANDSINK | gaz naturel 5
2 x OutPort_1425478 | SOURCEANDSINK | gaz naturel 5
2 x InPort_1423220 | SOURCEANDSINK | gaz naturel 5
OutPort_1423232 | SOURCEANDSINK | gaz naturel 5
InPort_1424593 | SINK | gaz naturel 5
OutPort_1424600 | SOURCE | gaz naturel 5
InPort_1424597 | SINK | gaz naturel 5
OutPort_1424593 | SOURCE | gaz naturel 5
2 x InPort_1424595 | SOURCEANDSINK | gaz naturel 5
2 x OutPort_1425477 | SOURCEANDSINK | gaz naturel 5
OutPort_1424597 | SOURCEANDSINK | gaz naturel 5
2 x InPort_1424791 | SOURCEANDSINK | gaz naturel 5
OutPort_1425431 | SOURCEANDSINK | gaz naturel 5
2 x OutPort_1425442 | SOURCEANDSINK | gaz naturel 5
Port_1424920 | SOURCEANDSINK | gaz naturel 5
InPort_1424920 | SOURCEANDSINK | gaz naturel 5
OutPort_1425151 | SOURCEANDSINK | gaz naturel 5
InPort_1425151 | SOURCEANDSINK | gaz naturel 5
OutPort_1425227 | SOURCEANDSINK | gaz naturel 5
InPort_1425225 | SINK | gaz naturel 5
OutPort_1425431 | SOURCE | gaz naturel 5
InPort_1425229 | SINK | gaz naturel 5
OutPort_1425225 | SOURCE | gaz naturel 5
InPort_1425227 | SOURCEANDSINK | gaz naturel 5
OutPort_1425229 | SOURCEANDSINK | gaz naturel 5
2 x InPort_1425434 | SOURCEANDSINK | gaz naturel 5
OutPort_1425450 | SOURCEANDSINK | gaz naturel 5
2 x InPort_1425444 | SOURCEANDSINK | gaz naturel 5
OutPort_1425519 | SOURCEANDSINK | gaz naturel 5
2 x OutPort_1425482 | SOURCEANDSINK | gaz naturel 5
InPort_1425450 | SOURCEANDSINK | gaz naturel 5
2 x OutPort_1432380 | SOURCEANDSINK | gaz naturel 5
2 x InPort_1425454 | SOURCEANDSINK | gaz naturel 5
InPort_1425477 | SOURCEANDSINK | gaz naturel 5
InPort_1425513 | SINK | gaz naturel 5
OutPort_1425519 | SOURCE | gaz naturel 5
InPort_1425517 | SINK | gaz naturel 5
OutPort_1425513 | SOURCE | gaz naturel 5
2 x InPort_1425515 | SOURCEANDSINK | gaz naturel 5
OutPort_1425517 | SOURCEANDSINK | gaz naturel 5
2 x OutPort_1432379 | SOURCEANDSINK | gaz naturel 5
InPort_1429290 | SINK | gaz naturel 3
OutPort_1429338 | SOURCE | gaz naturel 3
InPort_1429335 | SINK | gaz naturel 3
OutPort_1429290 | SOURCE | gaz naturel 3
InPort_1429333 | SOURCEANDSINK | gaz naturel 3
OutPort_1429335 | SOURCEANDSINK | gaz naturel 3
Port_1430730 | SOURCE | gaz naturel 4
InPort_1430730 | SOURCEANDSINK | gaz naturel 4
2 x OutPort_1431047 | SOURCEANDSINK | gaz naturel 4
2 x InPort_1431026 | SOURCEANDSINK | gaz naturel 4
2 x OutPort_1432164 | SOURCEANDSINK | gaz naturel 4
2 x Port_1431917 | SOURCEANDSINK
InPort_1432158 | SOURCEANDSINK | gaz naturel 4
Port_1432158 | SOURCEANDSINK | gaz naturel 4
2 x InPort_1432371 | SOURCEANDSINK | gaz naturel 5
2 x OutPort_1432389 | SOURCEANDSINK | gaz naturel 5
InPort_1432379 | SOURCEANDSINK | gaz naturel 5
2 x InPort_1432383 | SOURCEANDSINK | gaz naturel 5
2 x OutPort_1432585 | SOURCEANDSINK | gaz naturel 5
Port_1432540 | SOURCEANDSINK | gaz naturel 5
InPort_1432540 | SOURCEANDSINK | gaz naturel 5
2 x Port_1433220 | SOURCEANDSINK

# IfcDoor: Int. Double:PP (1.16m x 2.04m), Int. Double:PP (1.16m x 2.04m):735926
In: Niveau 1
Type - ParameterTakesPrecedence: no; Sizeable: no; Material: Bois - Panneau de porte (2), Finition Peinture - Blanc satiné (4), Bois - Cadre de porte (3)
Type - Pset_DoorCommon - IsExternal: no; ThermalTransmittance: 3.6886 kg/K/s3
OverallHeight: 2075 mm; OverallWidth: 1230 mm
Pset_DoorCommon - Reference: PP (1.16m x 2.04m)
Pset_QuantityTakeOff - Reference: PP (1.16m x 2.04m)

# IfcDoor: Int. Double:PP (1.26m x 2.04m), Int. Double:PP (1.26m x 2.04m):734472
In: Niveau 0
Type - ParameterTakesPrecedence: no; Sizeable: no; Material: Bois - Panneau de porte (2), Finition Peinture - Blanc satiné (4), Bois - Cadre de porte (3)
Type - Pset_DoorCommon - IsExternal: no; ThermalTransmittance: 3.6886 kg/K/s3
OverallHeight: 2075 mm; OverallWidth: 1330 mm
Pset_DoorCommon - Reference: PP (1.26m x 2.04m)
Pset_QuantityTakeOff - Reference: PP (1.26m x 2.04m)

# IfcDoor: Int. Double:PP (1.46m x 2.04m) (2)
In: Niveau 0
Type - ParameterTakesPrecedence: no; Sizeable: no; Material: Bois - Panneau de porte (2), Finition Peinture - Blanc satiné (4), Bois - Cadre de porte (3)
Type - Pset_DoorCommon - IsExternal: no; ThermalTransmittance: 3.6886 kg/K/s3
OverallHeight: 2075 mm; OverallWidth: 1530 mm
Pset_DoorCommon - Reference: PP (1.46m x 2.04m)
Pset_QuantityTakeOff - Reference: PP (1.46m x 2.04m)
Name (Int. Double:PP (1.46m x 2.04m):...)
734534
734575 | Material: Bois - Panneau de porte, Finition Peinture - Blanc satiné, Bois - Cadre de porte

# IfcDoor: Int. Simple:PP (0.83m x 2.04m) (2)
Type - OperationType: SINGLE_SWING_LEFT; ParameterTakesPrecedence: no; Sizeable: no; Material: Finition Peinture - Blanc satiné (4), Bois - Panneau de porte, Bois - Cadre de porte (3)
Type - Int. Simple:PP (0.83m x 2.04m):734273:1 - PanelOperation: SWINGING
Type - Pset_DoorCommon - IsExternal: no; ThermalTransmittance: 3.7021 kg/K/s3
OverallHeight: 2075 mm; OverallWidth: 900 mm
Pset_DoorCommon - Reference: PP (0.83m x 2.04m)
Pset_QuantityTakeOff - Reference: PP (0.83m x 2.04m)
Name (Int. Simple:PP (0.83m x 2.04m):...) | In
734273 | Niveau 0
735665 | Niveau 1 | Material: Finition Peinture - Blanc satiné, Bois - Panneau de porte, Bois - Cadre de porte

# IfcDoor: Int. Simple:PP (0.83m x 2.04m), Int. Simple:PP (0.83m x 2.04m):735553
In: Niveau 1
Type - OperationType: SINGLE_SWING_RIGHT; ParameterTakesPrecedence: no; Sizeable: no; Material: Finition Peinture - Blanc satiné (4), Bois - Panneau de porte, Bois - Cadre de porte (3)
Type - Int. Simple:PP (0.83m x 2.04m):735553:1 - PanelOperation: SWINGING
Type - Pset_DoorCommon - IsExternal: no; ThermalTransmittance: 3.7021 kg/K/s3
OverallHeight: 2075 mm; OverallWidth: 900 mm
Pset_DoorCommon - Reference: PP (0.83m x 2.04m)
Pset_QuantityTakeOff - Reference: PP (0.83m x 2.04m)

# IfcDoor: Int. Simple:PP (0.83m x 2.04m) (3)
In: Niveau 1
Type - OperationType: SINGLE_SWING_RIGHT; ParameterTakesPrecedence: no; Sizeable: no; Material: Finition Peinture - Blanc satiné (4), Bois - Panneau de porte, Bois - Cadre de porte (3)
Type - Int. Simple:PP (0.83m x 2.04m):735747:1 - PanelOperation: SWINGING
Type - Pset_DoorCommon - IsExternal: no; ThermalTransmittance: 3.7021 kg/K/s3
OverallHeight: 2075 mm; OverallWidth: 900 mm
Pset_DoorCommon - Reference: PP (0.83m x 2.04m)
Pset_QuantityTakeOff - Reference: PP (0.83m x 2.04m)
Name (Int. Simple:PP (0.83m x 2.04m):...) | Material
735747
810380 | Finition Peinture - Blanc satiné, Bois - Panneau de porte, Bois - Cadre de porte
978431 | Finition Peinture - Blanc satiné, Bois - Panneau de porte, Bois - Cadre de porte

# IfcFlowController: Balancing_valve-Caleffi-130_DN15-DN50:vanne TA strad 32 (1) (2)
In: Niveau 0
Type - Classification: D30 HVAC (Uniformat); Material: Technopolymer Grey (2), Technopolymer Black, Metal Brass (16)
Type - Pset_DuctConnection - ConnectionType: Gas ISO 228-1
Type - Pset_ManufacturerTypeInformation - Manufacturer: Caleffi Italy
Type - Pset_PipeConnection - ConnectionType: Gas ISO 228-1
Pset_DistributionFlowElementCommon - Reference: vanne TA strad 32 (1); sets with these values: 2
Name (Balancing_valve-Caleffi-130_DN15-DN50:vanne TA strad 32 (1):...) | Group
1317772 | Chauffage retour primaire 1
1365801 | Chauffage aller 8

# IfcFlowController: Ball_Valves-Full_Port-WATTS-C-FBV-1_Series:C-FBV-1_1 1/4" (3)
In: Niveau 0
Type - Classification: D2090900 Misc. Other Plumbing Systems (Uniformat); Material: Metal-WATTS-Carbon Steel-ASTM A216 gr.WCB (2), Metal-WATTS-Carbon Steel-AISI 304 with Vinyl Insulator
Type - Pset_DuctConnection - ConnectionType: NPT Connection
Type - Pset_ManufacturerTypeInformation - Manufacturer: WATTS
Type - Pset_PipeConnection - ConnectionType: NPT Connection
Pset_DistributionFlowElementCommon - Reference: C-FBV-1_1 1/4"; sets with these values: 2
Group: gaz naturel 5
Name (Ball_Valves-Full_Port-WATTS-C-FBV-1_Series:C-FBV-1_1 1/4":...) | Material
1424593
1425225 | Metal-WATTS-Carbon Steel-ASTM A216 gr.WCB, Metal-WATTS-Carbon Steel-AISI 304 with Vinyl Insulator
1425513 | Metal-WATTS-Carbon Steel-ASTM A216 gr.WCB, Metal-WATTS-Carbon Steel-AISI 304 with Vinyl Insulator

# IfcFlowController: Ball_Valves-Full_Port-WATTS-C-FBV-1_Series:C-FBV-1_3/4", Ball_Valves-Full_Port-WATTS-C-FBV-1_Series:C-FBV-1_3/4":1429290
In: Niveau 0
Type - Classification: D2090900 Misc. Other Plumbing Systems (Uniformat); Material: Metal-WATTS-Carbon Steel-ASTM A216 gr.WCB (2), Metal-WATTS-Carbon Steel-AISI 304 with Vinyl Insulator
Type - Pset_DuctConnection - ConnectionType: NPT Connection
Type - Pset_ManufacturerTypeInformation - Manufacturer: WATTS
Type - Pset_PipeConnection - ConnectionType: NPT Connection
Pset_DistributionFlowElementCommon - Reference: C-FBV-1_3/4"; sets with these values: 2
Group: gaz naturel 3

# IfcFlowController: FFGASB_2:01BTA03, FFGASB_2:01BTA03:1421369
In: Niveau 0
Type - Material: Nickel (10), Render Material 255-255-255 (7), RGB 255-255-000 (5)
Type - Pset_ManufacturerTypeInformation - Manufacturer: SOPAL
Pset_DistributionFlowElementCommon - Reference: 01BTA03; sets with these values: 2
Group: gaz naturel 1

# IfcFlowController: Gaz naturel - Filtre gaz:DN 20, Gaz naturel - Filtre gaz:DN 20:1430730
In: Niveau 0
Type - Material: Métal (4)
Pset_DistributionFlowElementCommon - Reference: DN 20; sets with these values: 2
Group: gaz naturel 4

# IfcFlowController: MEP_PipeAccessories_IBP_Conex_BallValve_1200:120050RRR250606 3/4" (2)
In: Niveau 0
Type - Classification: D20 Plumbing (Uniformat); Material: Stainless Steel, Polished, Polyethylene, High Density, Steel, DZR Brass (EN 12165 CW602N) (4), Clearance Zone
Type - Pset_ElementShading - Color: n/a
Type - Pset_ManufacturerTypeInformation - ModelReference: 3/4" - 120050; Manufacturer: Conex Banninger; ProductionYear: n/a
Pset_DistributionFlowElementCommon - Reference: 120050RRR250606 3/4"; sets with these values: 2
Pset_ManufacturerOccurrence - BarCode: Please Record On Commissioning.; SerialNumber: Please Record On Commissioning.
Name (MEP_PipeAccessories_IBP_Conex_BallValve_1200:120050RRR250606 3/4":...)
1318955
1320349 | Material: Stainless Steel, Polished, Polyethylene, High Density, Steel, DZR Brass (EN 12165 CW602N), Clearance Zone

# IfcFlowController: MEP_PipeAccessories_IBP_Conex_BallValve_1200:120050RRR251616 2" (2)
In: Niveau 0
Type - Classification: D20 Plumbing (Uniformat); Material: Stainless Steel, Polished, Polyethylene, High Density, Steel, DZR Brass (EN 12165 CW602N) (4), Clearance Zone
Type - Pset_ElementShading - Color: n/a
Type - Pset_ManufacturerTypeInformation - ModelReference: 2" - 120050; Manufacturer: Conex Banninger; ProductionYear: n/a
Pset_DistributionFlowElementCommon - Reference: 120050RRR251616 2"; sets with these values: 2
Pset_ManufacturerOccurrence - BarCode: Please Record On Commissioning.; SerialNumber: Please Record On Commissioning.
Name (MEP_PipeAccessories_IBP_Conex_BallValve_1200:120050RRR251616 2":...) | Group
1366583 | Chauffage aller 9
1366793 | Chauffage retour primaire 1 | Material: Stainless Steel, Polished, Polyethylene, High Density, Steel, DZR Brass (EN 12165 CW602N), Clearance Zone

# IfcFlowController: Plumbing_Valves_Brymec_38937_Wafer_Butterfly_Valve _Ductile_Iron_WRAS_PN16_3_Inch:38937 - 3" Ductile Iron Wafer Butterfly Valve - WRAS (5)
In: Niveau 0
Type - Material: Default, Iron, Malleable, Steel, Paint Finish, Blue (8), Brymec Black Sealant (4), <Unnamed>, Brymec Blue Cast Iron (7), Brymec Chrome
Type - Pset_ManufacturerTypeInformation - Manufacturer: Brymec Ltd
Pset_DistributionFlowElementCommon - Reference: 38937 - 3" Ductile Iron Wafer Butterfly Valve - WRAS; sets with these values: 2
Name (Plumbing_Valves_Brymec_38937_Wafer_Butterfly_Valve _Ductile_Iron_WRAS_PN16_3_Inch:38937 - 3" Ductile Iron Wafer Butterfly Valve - WRAS:...) | Material | Group
1272783
1276066 | Default, Iron, Malleable, Steel, Paint Finish, Blue, Brymec Black Sealant, <Unnamed>, Brymec Blue Cast Iron, Brymec Chrome | Chauffage aller 5
1276212 |  | Chauffage retour 3
1276245 | Default, Iron, Malleable, Steel, Paint Finish, Blue, Brymec Black Sealant, <Unnamed>, Brymec Blue Cast Iron, Brymec Chrome | Chauffage retour primaire 2
1298861 | Default, Iron, Malleable, Steel, Paint Finish, Blue, Brymec Black Sealant, <Unnamed>, Brymec Blue Cast Iron, Brymec Chrome | Chauffage aller 5

# IfcFlowController: Plumbing_Valves_LK-Systems_LK-840-ThermoMix-20-Female-25-40:F 2 ", Plumbing_Valves_LK-Systems_LK-840-ThermoMix-20-Female-25-40:F 2 ":1353682
In: Niveau 0
Type - Classification: D2090 Other Plumbing Systems (Uniformat); Material: Steel - LK Systems - Secondary (5), Steel - LK Systems - Red, Steel - LK Systems - Black, Brass -LK Systems - Brushed (4)
Type - Pset_ManufacturerTypeInformation - ArticleNumber: 181918; Manufacturer: LK Systems
Pset_DistributionFlowElementCommon - Reference: F 2 "; sets with these values: 2
Group: Chauffage retour primaire 1

# IfcFlowController: Pressure_Gauge-AGF-Model_7500:Model 7500 (2)
In: Niveau 0
Type - Classification: D4030900 Other Fire Protection Specialties (Uniformat); Material: Plastic-AGF-White, Metal-AGF-Brass, Plastic-AGF-Black
Type - Pset_ManufacturerTypeInformation - Manufacturer: AGF Manufacturing
Pset_DistributionFlowElementCommon - Reference: Model 7500; sets with these values: 2
Name (Pressure_Gauge-AGF-Model_7500:Model 7500:...)
1250934
1251988

# IfcFlowController: Purgeur _Caleffi_5020_5021 DN10 DN15:1/2'' (5)
In: Niveau 0
Type - Material: Metal - Caleffi - Brass, Technopolymer - Caleffi - Black
Type - Pset_DuctConnection - ConnectionType: Gas ISO 228/1
Type - Pset_ManufacturerTypeInformation - Manufacturer: Caleffi Italy
Type - Pset_PipeConnection - ConnectionType: Gas ISO 228/1
Material: Technopolymer - Caleffi - Black, Metal - Caleffi - Brass
Pset_DistributionFlowElementCommon - Reference: 1/2''; sets with these values: 2
Name (Purgeur _Caleffi_5020_5021 DN10 DN15:1/2'':...)
1299774
1300453
1301314
1301603
1384537

# IfcFlowController: Purgeur _Caleffi_5020_5021 DN10 DN15:1/2''_Automatic shut-off cock, Purgeur _Caleffi_5020_5021 DN10 DN15:1/2''_Automatic shut-off cock:1240949
In: Niveau 0
Type - Material: Metal - Caleffi - Brass
Type - Pset_DuctConnection - ConnectionType: Gas ISO 228/1
Type - Pset_ManufacturerTypeInformation - Manufacturer: Caleffi Italy
Type - Pset_PipeConnection - ConnectionType: Gas ISO 228/1
Material: Metal - Caleffi - Brass, Technopolymer - Caleffi - Black
Pset_DistributionFlowElementCommon - Reference: 1/2''_Automatic shut-off cock; sets with these values: 2

# IfcFlowController: Purgeur _Caleffi_5020_5021 DN10 DN15:3/8''_Automatic shut-off cock_Chrome (2)
In: Niveau 0
Type - Material: Metal - Caleffi - Brass Chrome
Type - Pset_DuctConnection - ConnectionType: Gas ISO 228/1
Type - Pset_ManufacturerTypeInformation - Manufacturer: Caleffi Italy
Type - Pset_PipeConnection - ConnectionType: Gas ISO 228/1
Pset_DistributionFlowElementCommon - Reference: 3/8''_Automatic shut-off cock_Chrome; sets with these values: 2
Name (Purgeur _Caleffi_5020_5021 DN10 DN15:3/8''_Automatic shut-off cock_Chrome:...)
1249217
1253088

# IfcFlowController: Safety relief valve_Caleffi_311 DN15:1/2'' 2.5 bar, Safety relief valve_Caleffi_311 DN15:1/2'' 2.5 bar:1409053
In: Niveau 0
Type - Classification: D30 HVAC (Uniformat); Material: Technopolymer - Caleffi - Red, Metal - Caleffi - Brass, Technopolymer - Caleffi - Black, Metal - Caleffi - Alluminium
Type - Pset_DuctConnection - ConnectionType: Gas ISO 228/1
Type - Pset_ManufacturerTypeInformation - Manufacturer: Caleffi Italy
Type - Pset_PipeConnection - ConnectionType: Gas ISO 228/1
Material: Metal - Caleffi - Brass, Technopolymer - Caleffi - Red, Technopolymer - Caleffi - Black, Metal - Caleffi - Alluminium; Group: Chauffage aller 10
Pset_DistributionFlowElementCommon - Reference: 1/2'' 2.5 bar; sets with these values: 2

# IfcFlowController: Soupape de sécurité_Caleffi_311 DN20:3/4'' 6 bar, Soupape de sécurité_Caleffi_311 DN20:3/4'' 6 bar:1248396
In: Niveau 0
Type - Classification: D30 HVAC (Uniformat); Material: Metal - Caleffi - Brass, Metal - Caleffi - Alluminium, Technopolymer - Caleffi - Red, Technopolymer - Caleffi - Black
Type - Pset_DuctConnection - ConnectionType: Gas ISO 228/1
Type - Pset_ManufacturerTypeInformation - Manufacturer: Caleffi Italy
Type - Pset_PipeConnection - ConnectionType: Gas ISO 228/1
Material: Technopolymer - Caleffi - Red, Metal - Caleffi - Alluminium, Technopolymer - Caleffi - Black, Metal - Caleffi - Brass
Pset_DistributionFlowElementCommon - Reference: 3/4'' 6 bar; sets with these values: 2

# IfcFlowController: Soupape de sécurité_Caleffi_311 DN20:3/4'' 7 bar, Soupape de sécurité_Caleffi_311 DN20:3/4'' 7 bar:1253587
In: Niveau 0
Type - Classification: D30 HVAC (Uniformat); Material: Metal - Caleffi - Brass, Metal - Caleffi - Alluminium, Technopolymer - Caleffi - Red, Technopolymer - Caleffi - Black
Type - Pset_DuctConnection - ConnectionType: Gas ISO 228/1
Type - Pset_ManufacturerTypeInformation - Manufacturer: Caleffi Italy
Type - Pset_PipeConnection - ConnectionType: Gas ISO 228/1
Material: Technopolymer - Caleffi - Red, Metal - Caleffi - Alluminium, Technopolymer - Caleffi - Black, Metal - Caleffi - Brass
Pset_DistributionFlowElementCommon - Reference: 3/4'' 7 bar; sets with these values: 2

# IfcFlowController: Valve-Ball-Isolation-Caleffi-LF_Brass-NA108:ERROR_LOAD TYPE CATALOG (2)
In: Niveau 0
Type - Classification: D3040 Distribution Systems (Uniformat); Material: Plastic - Caleffi - Black, Metal - Caleffi - Stainless Steel (2), Metal - Caleffi - Brass (6)
Type - Pset_DuctConnection - ConnectionType: NPT Female
Type - Pset_ManufacturerTypeInformation - Manufacturer: Caleffi North America, Inc.
Type - Pset_PipeConnection - ConnectionType: NPT Female
Pset_DistributionFlowElementCommon - Reference: ERROR_LOAD TYPE CATALOG; sets with these values: 2
Name (Valve-Ball-Isolation-Caleffi-LF_Brass-NA108:ERROR_LOAD TYPE CATALOG:...) | Group
1310541 | Chauffage retour primaire 1
1319683 | Chauffage aller 9 | Material: Plastic - Caleffi - Black, Metal - Caleffi - Stainless Steel, Metal - Caleffi - Brass

# IfcFlowFitting: Chapeau - Générique:Standard (8)
In: Niveau 0
Type - Material: <Unnamed>
Pset_DistributionFlowElementCommon - Reference: Standard; sets with these values: 2
Name (Chapeau - Générique:Standard:...) | Group
1226085 | Chauffage aller 1
1226088 | Chauffage aller 1
1226918 | Chauffage retour 3
1233118 | Chauffage aller 5
1234350 | Chauffage retour primaire 2
1235854 | Chauffage aller primaire 1
1409667 | gaz naturel 2
1409669 | gaz naturel 2

# IfcFlowFitting: Circul - Std - Coude - ALDES - STANDARD - (Ba) (1):Standard, Circul - Std - Coude - ALDES - STANDARD - (Ba) (1):Standard:750958
In: Niveau 1
Type - Classification: D3040100 Air Distribution Systems (Uniformat); Material: <Unnamed> (3)
Type - Pset_ManufacturerTypeInformation - Manufacturer: ALDES
Pset_DistributionFlowElementCommon - Reference: Standard; sets with these values: 2
Group: Génie climatique Soufflage 1

# IfcFlowFitting: Circul - Std - Reduction conique - ALDES - STANDARD - (Ba) (1):Standard (7)
In: Niveau 1
Type - Material: <Unnamed> (3)
Type - Pset_ManufacturerTypeInformation - Manufacturer: ALDES
Pset_DistributionFlowElementCommon - Reference: Standard; sets with these values: 2
Group: Génie climatique Soufflage 1
Name (Circul - Std - Reduction conique - ALDES - STANDARD - (Ba) (1):Standard:...)
750837
750882
750918
750949
753417 | Material: <Unnamed>
753441 | Material: <Unnamed>
753454

# IfcFlowFitting: Circul - Std - Té - ALDES - STANDARD - (Ba) (1):Standard (2)
In: Niveau 1
Type - Classification: D3040100 Air Distribution Systems (Uniformat); Material: <Unnamed> (4)
Type - Pset_ManufacturerTypeInformation - Manufacturer: ALDES
Pset_DistributionFlowElementCommon - Reference: Standard; sets with these values: 2
Group: Génie climatique Soufflage 1
Name (Circul - Std - Té - ALDES - STANDARD - (Ba) (1):Standard:...)
750978
753475

# IfcFlowFitting: Conex-Series 3000-Reduction Nipple TO:3245016012000, Conex-Series 3000-Reduction Nipple TO:3245016012000:1400764
In: Niveau 0
Type - Material: Copper Conex (3)
Type - Pset_ManufacturerTypeInformation - Manufacturer: Conex Banninger
Type - Pset_ProductRequirements - Name: Series 3000; Category: Copper pipeline fittings
Pset_DistributionFlowElementCommon - Reference: 3245016012000; sets with these values: 2
Group: Chauffage retour primaire 1

# IfcFlowFitting: Conex-Series 8000_8092:8092 M06000000, Conex-Series 8000_8092:8092 M06000000:1383094
In: Niveau 0
Type - Material: Copper Conex (12)
Type - Pset_ManufacturerTypeInformation - Manufacturer: Conex Banninger
Type - Pset_ProductRequirements - Name: Series 8000; Category: Copper pipeline fittings
Pset_DistributionFlowElementCommon - Reference: 8092 M06000000; sets with these values: 2
Group: Chauffage aller 10

# IfcFlowFitting: Conex-Series 8000_8280:8280 010000000 (4)
In: Niveau 0
Type - Material: Copper Conex
Type - Pset_ManufacturerTypeInformation - Manufacturer: Conex Banninger
Type - Pset_ProductRequirements - Name: Series 8000; Category: Copper pipeline fittings
Pset_DistributionFlowElementCommon - Reference: 8280 010000000; sets with these values: 2
Group: Chauffage retour primaire 1
Name (Conex-Series 8000_8280:8280 010000000:...)
1362083
1362710
1362819
1363900

# IfcFlowFitting: Conex-Series 8000_8280:8280 012000000, Conex-Series 8000_8280:8280 012000000:1364620
In: Niveau 0
Type - Material: Copper Conex
Type - Pset_ManufacturerTypeInformation - Manufacturer: Conex Banninger
Type - Pset_ProductRequirements - Name: Series 8000; Category: Copper pipeline fittings
Pset_DistributionFlowElementCommon - Reference: 8280 012000000; sets with these values: 2
Group: Chauffage retour primaire 1

# IfcFlowFitting: Conex-Series 8000_8280:8280 016000000 (3)
In: Niveau 0
Type - Material: Copper Conex
Type - Pset_ManufacturerTypeInformation - Manufacturer: Conex Banninger
Type - Pset_ProductRequirements - Name: Series 8000; Category: Copper pipeline fittings
Pset_DistributionFlowElementCommon - Reference: 8280 016000000; sets with these values: 2
Name (Conex-Series 8000_8280:8280 016000000:...) | Group
1364875 | Chauffage retour primaire 1
1364973 | Chauffage retour primaire 1
1365286 | Chauffage aller 8

# IfcFlowFitting: Coude - Générique:Standard (52)
In: Niveau 0
Type - Material: <Unnamed> (2)
Pset_DistributionFlowElementCommon - Reference: Standard; sets with these values: 2
Name (Coude - Générique:Standard:...) | Group | Material
1229989 | Chauffage retour 3; Chauffage aller 4
1230780 | Chauffage retour 3 | <Unnamed>
1231029 | Chauffage aller 3 | <Unnamed>
1231069 | Chauffage aller 3 | <Unnamed>
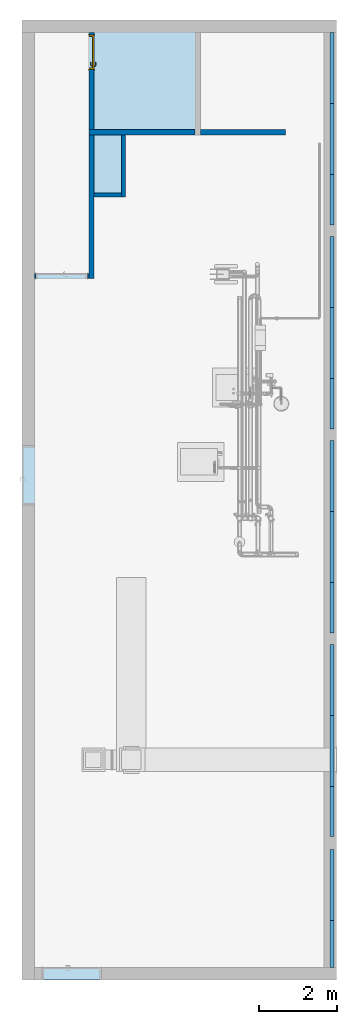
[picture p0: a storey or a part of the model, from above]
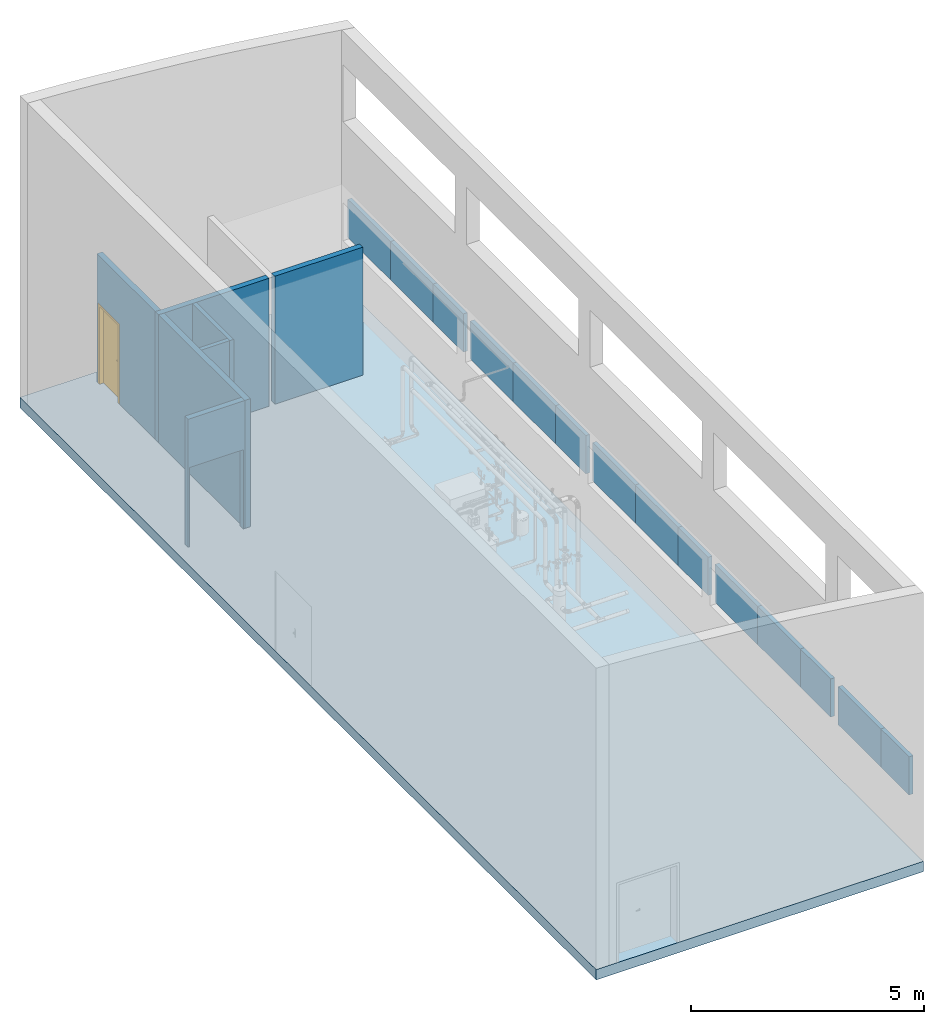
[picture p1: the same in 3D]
Properties of the parts of a building model (IFC2X3), part 2 of 2

# IfcFlowFitting: Coude - Générique:Standard (52)
Name (Coude - Générique:Standard:...) | Group | Material
1231071 | Chauffage aller 3 | <Unnamed>
1233212 | Chauffage aller 5 | <Unnamed>
1233302 | Chauffage aller 5
1233546 | Chauffage aller 5 | <Unnamed>
1233780 | Chauffage retour primaire 2 | <Unnamed>
1234849 | Chauffage retour primaire 2 | <Unnamed>
1234851 | Chauffage retour primaire 2; Chauffage retour primaire 1 | <Unnamed>
1235543 | Chauffage retour primaire 1 | <Unnamed>
1235545 | Chauffage retour primaire 1 | <Unnamed>
1237930 | Chauffage aller 6
1238240 | Chauffage retour primaire 1 | <Unnamed>
1238373 | Chauffage retour primaire 1 | <Unnamed>
1238960 | Chauffage retour primaire 2 | <Unnamed>
1239957 | Chauffage aller primaire 4
1247586 | Chauffage aller 5; Chauffage retour 2 | <Unnamed>
1247724 | Chauffage aller 3 | <Unnamed>
1247731 | Chauffage aller 3 | <Unnamed>
1247733 | Chauffage aller 3 | <Unnamed>
1248134 | Chauffage retour 1
1248173 | Chauffage retour 1 | <Unnamed>
1251134 | Chauffage retour 5 | <Unnamed>
1251160 | Chauffage retour 5 | <Unnamed>
1262222 | Chauffage aller primaire 4 | <Unnamed>
1262224 | Chauffage aller primaire 4 | <Unnamed>
1301418 | Chauffage aller 5 | <Unnamed>
1301420 | Chauffage aller 5
1318692 | Chauffage retour primaire 1; Chauffage aller 7 | <Unnamed>
1318694 | Chauffage retour primaire 1 | <Unnamed>
1319207 | Chauffage aller 9 | <Unnamed>
1319215 | Chauffage aller 9 | <Unnamed>
1319417 | Chauffage aller 9 | <Unnamed>
1383826 | Chauffage aller 10 | <Unnamed>
1383830 | Chauffage aller 10 | <Unnamed>
1409276 | gaz naturel 1
1409793 | gaz naturel 1 | <Unnamed>
1409822 | gaz naturel 1 | <Unnamed>
1409838 | gaz naturel 1 | <Unnamed>
1421565 | gaz naturel 3 | <Unnamed>
1423018 | gaz naturel 5
1423218 | gaz naturel 5 | <Unnamed>
1423235 | gaz naturel 5 | <Unnamed>
1425151 | gaz naturel 5 | <Unnamed>
1425442 | gaz naturel 5 | <Unnamed>
1425450 | gaz naturel 5 | <Unnamed>
1425482 | gaz naturel 5 | <Unnamed>
1432164 | gaz naturel 4
1432389 | gaz naturel 5 | <Unnamed>
1432585 | gaz naturel 5 | <Unnamed>

# IfcFlowFitting: Coude rectangulaire - Rayon constant - Bridé:100 R (7)
Type - Material: <Unnamed> (5)
Pset_DistributionFlowElementCommon - Reference: 100 R; sets with these values: 2
Name (Coude rectangulaire - Rayon constant - Bridé:100 R:...) | In | Group
755218 | Niveau 1 | Génie climatique Soufflage 1
755273 | Niveau 1 | Génie climatique Soufflage 1
757967 | Niveau 1 | Génie climatique Soufflage 1 | Material: <Unnamed>
758134 | Niveau 1 | Génie climatique Reprise 2 | Material: <Unnamed>
758431 | Niveau 0 | Génie climatique Reprise 2
758504 | Niveau 1 | Génie climatique Reprise 2 | Material: <Unnamed>
764588 | Niveau 0 | Génie climatique Air Neuf 1

# IfcFlowFitting: Gaine RE RU - Joint coulissant:Standard, Gaine RE RU - Joint coulissant:Standard:755056
In: Niveau 1
Type - Material: <Unnamed> (3)
Pset_DistributionFlowElementCommon - Reference: Standard; sets with these values: 2
Group: Génie climatique Soufflage 1

# IfcFlowFitting: Piquage Acier Noir droit:Longueur = 25 (14)
In: Niveau 0
Type - Material: <Unnamed>
Pset_DistributionFlowElementCommon - Reference: Longueur = 25; sets with these values: 2
Name (Piquage Acier Noir droit:Longueur = 25:...) | Group
1238229 | Chauffage retour primaire 1
1238957 | Chauffage retour primaire 2
1239954 | Chauffage aller primaire 4
1248059 | Chauffage retour 1
1248155 | Chauffage retour 1
1300048 | Chauffage aller primaire 4
1300229 | Chauffage aller 2
1300699 | Chauffage aller 5
1301528 | Chauffage aller 3
1311610 | Chauffage aller 6
1318892 | Chauffage aller 7
1320291 | Chauffage aller 9
1384212 | Chauffage aller 10
1409150 | Chauffage aller 10

# IfcFlowFitting: Piquage Aldes:Standard (6)
In: Niveau 1
Type - Material: <Unnamed> (3)
Pset_DistributionFlowElementCommon - Reference: Standard; sets with these values: 2
Group: Génie climatique Soufflage 1
Name (Piquage Aldes:Standard:...)
752768
752774
752785
754090
754103
754116 | Material: <Unnamed>

# IfcFlowFitting: Transformation - Générique:Standard (42)
In: Niveau 0
Type - Material: <Unnamed>
Pset_DistributionFlowElementCommon - Reference: Standard; sets with these values: 2
Name (Transformation - Générique:Standard:...) | Group
1238890 | Chauffage retour primaire 2
1247588 | Chauffage aller 5
1247673 | Chauffage retour 3; Chauffage aller 3
1247726 | Chauffage aller 3
1251086 | Chauffage retour 4
1252877
1276070 | Chauffage aller 5
1276216 | Chauffage retour 3
1276218 | Chauffage retour 3; Chauffage aller 3
1276388 | Chauffage retour primaire 2
1276390 | Chauffage retour primaire 2
1298984 | Chauffage aller 5
1311698 | Chauffage aller 6
1318675 | Chauffage retour primaire 2; Chauffage aller 7
1318957 | Chauffage aller 7
1319182 | Chauffage aller primaire 4
1320357 | Chauffage aller 9
1353096 | Chauffage retour primaire 1
1353099 | Chauffage retour primaire 1
1353686 | Chauffage retour primaire 1
1353689 | Chauffage retour primaire 1
1366078 | Chauffage aller 8
1366604 | Chauffage aller 9
1366607 | Chauffage aller 9
1366840 | Chauffage retour primaire 1
1366842 | Chauffage retour primaire 1
1383820 | Chauffage aller 10
1406723
1421413 | gaz naturel 1
1421416 | gaz naturel 1
1423020 | gaz naturel 5
1423232 | gaz naturel 5
1424597 | gaz naturel 5
1424600 | gaz naturel 5
1425229 | gaz naturel 5
1425431 | gaz naturel 5
1425517 | gaz naturel 5
1425519 | gaz naturel 5
1429335 | gaz naturel 3
1429338 | gaz naturel 3
1431047 | gaz naturel 4
1433431 | Chauffage retour primaire 1

# IfcFlowFitting: Transformation rectangulaire - Bridé:Standard (3)
Type - Material: <Unnamed> (5)
Pset_DistributionFlowElementCommon - Reference: Standard; sets with these values: 2
Name (Transformation rectangulaire - Bridé:Standard:...) | In | Group
757968 | Niveau 1 | Génie climatique Soufflage 1
758506 | Niveau 0 | Génie climatique Reprise 2
764589 | Niveau 0 | Génie climatique Air Neuf 1

# IfcFlowFitting: Té - Générique:Standard (4)
In: Niveau 0
Type - Material: <Unnamed>
Pset_DistributionFlowElementCommon - Reference: Standard; sets with these values: 2
Name (Té - Générique:Standard:...) | Group
1227514 | Chauffage retour 3
1233286 | Chauffage aller 5
1425477 | gaz naturel 5
1432379 | gaz naturel 5

# IfcFlowSegment: Canalisation:Acier gaz, Canalisation:Acier gaz:1409643
In: Niveau 0
Pset_DistributionFlowElementCommon - Reference: Acier gaz; sets with these values: 2
Pset_FlowSegmentDuctSegment - Length: 400 mm; sets with these values: 2
Group: gaz naturel 2

# IfcFlowSegment: Canalisation:tube acier (78)
In: Niveau 0
Pset_DistributionFlowElementCommon - Reference: tube acier; sets with these values: 2
Pset_FlowSegmentDuctSegment - sets with these values: 2
Name (Canalisation:tube acier:...) | Length (mm) | Group
1226026 | 800 | Chauffage aller 1
1227406 | 629.264 | Chauffage retour 3
1227422 | 761.5 | Chauffage retour 3
1227515 | 545.506 | Chauffage retour 3
1228611 | 172 | Chauffage aller 3
1228619 | 6069.56 | Chauffage aller 3
1229948 | 229.968 | Chauffage aller 4
1230697 | 1147.49 | Chauffage aller 3
1231015 | 117.943 | Chauffage aller 3
1232776 | 1664.99 | Chauffage aller 3
1232794 | 111.043 | Chauffage aller 5
1232892 | 860 | Chauffage aller 5
1233215 | 731.5 | Chauffage aller 5
1233287 | 301 | Chauffage aller 5
1233291 | 888.55 | Chauffage aller 5
1233352 | 172 | Chauffage aller 5
1233375 | 6165.5 | Chauffage aller 5
1233538 | 1588.62 | Chauffage aller 5
1233709 | 383.543 | Chauffage retour primaire 2
1233772 | 104.733 | Chauffage retour primaire 2
1233937 | 935.054 | Chauffage retour primaire 2
1234127 | 5549.49 | Chauffage aller 2; Chauffage retour primaire 1
1234299 | 5444.99 | Chauffage retour primaire 2; Chauffage retour primaire 1
1235533 | 42.5299 | Chauffage retour primaire 1
1235629 | 383.543 | Chauffage aller primaire 4
1235760 | 1406.02 | Chauffage aller primaire 4
1235770 | 5600.88 | Chauffage aller primaire 4
1237938 | 5.15198 | Chauffage retour primaire 1
1238232 | 190 | Chauffage retour primaire 1
1238361 | 298.711 | Chauffage retour primaire 1
1238876 | 632.265 | Chauffage retour primaire 2
1238888 | 175.171 | Chauffage retour primaire 2
1238893 | 1816.25 | Chauffage retour primaire 2
1238980 | 409.436 | Chauffage aller primaire 4
1238994 | 1098.58 | Chauffage aller primaire 4
1241064 | 120 | Chauffage aller primaire 3
1247532 | 250.35 | Chauffage retour 2
1247649 | 489.613 | Chauffage aller 3
1247722 | 65.4336 | Chauffage aller 3
1247777 | 143.778 | Chauffage retour 1
1247800 | 208.182 | Chauffage retour 1
1248126 | 64.091 | Chauffage retour 1
1248144 | 44.332 | Chauffage retour 1
1248165 | 64.091 | Chauffage retour 1
1251073 | 109 | Chauffage retour 4
1251114 | 208.182 | Chauffage retour 5
1251122 | 63.1545 | Chauffage retour 5
1251152 | 63.1545 | Chauffage retour 5
1251172 | 70.068 | Chauffage retour 5
1276068 | 434.325 | Chauffage aller 5
1276214 | 904.512 | Chauffage retour 3
1276386 | 676.5 | Chauffage retour primaire 2
1299923 | 64.483 | Chauffage aller primaire 4
1300102 | 55 | Chauffage aller 2
1300605 | 75 | Chauffage aller 5
1301440 | 74.9767 | Chauffage aller 3
1310578 | 12.4035 | Chauffage retour primaire 1
1311545 | 2.95932 | Chauffage aller 6
1317774 | 25.531 | Chauffage retour primaire 1
1318660 | 216 | Chauffage aller 7
1318690 | 182 | Chauffage retour primaire 1
1318855 | 14.4794 | Chauffage aller 7
1319134 | 161.02 | Chauffage aller 9
1319199 | 69.0661 | Chauffage aller 9
1319209 | 693.263 | Chauffage aller 9
1319377 | 76 | Chauffage aller 9
1319685 | 26.0236 | Chauffage aller primaire 4; Chauffage aller 9
1319756 | 46.5 | Chauffage aller 9
1353094 | 5.99823 | Chauffage retour primaire 1
1353684 | 69.0661 | Chauffage retour primaire 1
1354178 | 58 | Chauffage aller 8
1366602 | 623.036 | Chauffage aller 9
1366838 | 35.0661 | Chauffage retour primaire 1
1383509 | 40.7841 | Chauffage aller 10
1383810 | 292.343 | Chauffage aller 10
1383824 | 226.305 | Chauffage aller 10
1383955 | 6.08954 | Chauffage aller 10
1409132 | 17.3161 | Chauffage aller 10

# IfcFlowSegment: Canalisation:tuyau cuivre (28)
In: Niveau 0
Pset_DistributionFlowElementCommon - Reference: tuyau cuivre; sets with these values: 2
Pset_FlowSegmentDuctSegment - sets with these values: 2
Name (Canalisation:tuyau cuivre:...) | Length (mm) | Group
1409182 | 4465.79 | gaz naturel 1
1409265 | 146.336 | gaz naturel 1
1409806 | 1031.58 | gaz naturel 1
1409812 | 81.9659 | gaz naturel 1
1409824 | 351.577 | gaz naturel 1
1421411 | 40.9659 | gaz naturel 1
1421547 | 1343.15 | gaz naturel 3
1421557 | 180 | gaz naturel 3
1422871 | 510.932 | gaz naturel 5
1422933 | 25.4 | gaz naturel 5
1423208 | 31.8744 | gaz naturel 5
1423220 | 26.016 | gaz naturel 5
1424595 | 23.868 | gaz naturel 5
1424791 | 15.7883 | gaz naturel 5
1424920 | 125.788 | gaz naturel 5
1425227 | 4.95567 | gaz naturel 5
1425434 | 71.5766 | gaz naturel 5
1425444 | 268.305 | gaz naturel 5
1425454 | 53.7523 | gaz naturel 5
1425478 | 29.6967 | gaz naturel 5
1425515 | 82.1168 | gaz naturel 5
1429333 | 26.3769 | gaz naturel 3
1431026 | 38.3495 | gaz naturel 4
1432158 | 138.648 | gaz naturel 4
1432371 | 13.7523 | gaz naturel 5
1432380 | 82.1168 | gaz naturel 5
1432383 | 491.076 | gaz naturel 5
1432540 | 126.898 | gaz naturel 5

# IfcFlowSegment: Gaine circulaire:Té / Coude Aldes (13)
In: Niveau 1
Pset_DistributionFlowElementCommon - Reference: Té / Coude Aldes; sets with these values: 2
Pset_FlowSegmentDuctSegment - sets with these values: 2
Pset_DuctSegmentTypeCommon - Shape: ROUND
Group: Génie climatique Soufflage 1
Name (Gaine circulaire:Té / Coude Aldes:...) | Pset_FlowSegmentDuctSegment, Length (mm) = Pset_DuctSegmentTypeCommon, Length (mm)
750789 | 1050.74
750800 | 5.44747
750817 | 1056
750841 | 3386.3
750885 | 2837.25
750921 | 18.4475
750952 | 1700.74
753398 | 2.55253
753420 | 4308.45
753433 | 49.8029
753444 | 1801
753476 | 4831.2
753481 | 1693

# IfcFlowSegment: Gaine flexible circulaire:Souple - Circulaire piquage Aldes (9)
In: Niveau 1
Type - PredefinedType: FLEXIBLESEGMENT
Pset_DistributionFlowElementCommon - Reference: Souple - Circulaire piquage Aldes; sets with these values: 2
Group: Génie climatique Soufflage 1
Name (Gaine flexible circulaire:Souple - Circulaire piquage Aldes:...)
752765
752771
752782
752788
754087
754094
754097
754100
754113

# IfcFlowSegment: Gaine rectangulaire:Té / Coude à rayon bridé (12)
Pset_DistributionFlowElementCommon - Reference: Té / Coude à rayon bridé; sets with these values: 2
Pset_FlowSegmentDuctSegment - sets with these values: 3
Name (Gaine rectangulaire:Té / Coude à rayon bridé:...) | In | Length (mm) | Group
755057 | Niveau 1 | 400 | Génie climatique Soufflage 1
755245 | Niveau 1 | 413.531 | Génie climatique Soufflage 1
755256 | Niveau 1 | 400 | Génie climatique Soufflage 1
755277 | Niveau 1 | 385.736 | Génie climatique Soufflage 1
756472 | Niveau 1 | 2787.2 | Génie climatique Soufflage 1
758050 | Niveau 1 | 400 | Génie climatique Reprise 2
758130 | Niveau 1 | 485.09 | Génie climatique Reprise 2
758402 | Niveau 0 | 500 | Génie climatique Reprise 2
758424 | Niveau 0 | 105 | Génie climatique Reprise 2
758483 | Niveau 0 | 130 | Génie climatique Reprise 2
763721 | Niveau 0 | 300 | Génie climatique Air Neuf 1
763756 | Niveau 0 | 445 | Génie climatique Air Neuf 1

# IfcFlowTerminal: Diffuseur du soufflage - Circulaire - Plafond circulaire:D160, Diffuseur du soufflage - Circulaire - Plafond circulaire:D160:753971
In: Niveau 1
Type - Material: <Unnamed> (4)
Pset_DistributionFlowElementCommon - Reference: D160; sets with these values: 2
Group: Génie climatique Soufflage 1

# IfcFlowTerminal: Diffuseur du soufflage - Circulaire - Plafond circulaire:D200 (8)
In: Niveau 1
Type - Material: <Unnamed> (4)
Pset_DistributionFlowElementCommon - Reference: D200; sets with these values: 2
Group: Génie climatique Soufflage 1
Name (Diffuseur du soufflage - Circulaire - Plafond circulaire:D200:...) | Material
752171
752287 | <Unnamed>
752402 | <Unnamed>
752454 | <Unnamed>
753735 | <Unnamed>
753793 | <Unnamed>
753835 | <Unnamed>
753912 | <Unnamed>

# IfcFlowTerminal: Grille air neuf:400x400 (2)
In: Niveau 1
Type - Material: Acier - Galvanisé (11)
Pset_DistributionFlowElementCommon - Reference: 400x400; sets with these values: 2
Name (Grille air neuf:400x400:...)
762252
762397

# IfcFlowTerminal: Grille air neuf:600x300 mm, Grille air neuf:600x300 mm:763887
In: Niveau 0
Type - Material: Acier - Galvanisé (9)
Pset_DistributionFlowElementCommon - Reference: 600x300 mm; sets with these values: 2
Group: Génie climatique Air Neuf 1

# IfcFlowTerminal: Lampe de bureau:Néon 1.20 m (2)
In: Niveau 1
Type - Material: Peinture - Ivoire (4)
Pset_DistributionFlowElementCommon - Reference: Néon 1.20 m; sets with these values: 2
Name (Lampe de bureau:Néon 1.20 m:...)
824016
824088 | Material: Peinture - Ivoire

# IfcFurnishingElement: Bureau du professeur:1350mm x 640mm, Bureau du professeur:1350mm x 640mm:1175652
In: Niveau 1
Type - Material: Tissus - Orange (3), Métal - Chrome (9), Plastique - Noir (10), Bois - Mélaminé beige (4), Peinture - Rouge (8)
Pset_QuantityTakeOff - Reference: 1350mm x 640mm

# IfcFurnishingElement: Table et chaises - 1 élève:700mm x 550mm (11)
In: Niveau 1
Type - Material: Peinture - Rouge (6), Plastique - Noir (9), Bois - Hêtre
Pset_QuantityTakeOff - Reference: 700mm x 550mm
Name (Table et chaises - 1 élève:700mm x 550mm:...) | Material
1175643
1175644 | Peinture - Rouge, Plastique - Noir, Bois - Hêtre, Bois - Mélaminé beige
1175645 | Peinture - Rouge, Plastique - Noir, Bois - Hêtre, Bois - Mélaminé beige
1175646 | Peinture - Rouge, Plastique - Noir, Bois - Hêtre, Bois - Mélaminé beige
1175647 | Peinture - Rouge, Plastique - Noir, Bois - Hêtre, Bois - Mélaminé beige
1175648 | Peinture - Rouge, Plastique - Noir, Bois - Hêtre, Bois - Mélaminé beige
1175649 | Peinture - Rouge, Plastique - Noir, Bois - Hêtre, Bois - Mélaminé beige
1175650 | Peinture - Rouge, Plastique - Noir, Bois - Hêtre, Bois - Mélaminé beige
1175651 | Peinture - Rouge, Plastique - Noir, Bois - Hêtre, Bois - Mélaminé beige
1175687 | Peinture - Rouge, Plastique - Noir, Bois - Hêtre, Bois - Mélaminé beige
1175688 | Peinture - Rouge, Plastique - Noir, Bois - Hêtre, Bois - Mélaminé beige

# IfcFurnishingElement: Table et chaises - 2 élèves:1500 mm x 900 mm (10)
In: Niveau 1
Type - Material: Peinture - Rouge (10), Plastique - Noir (13), Bois - Hêtre (2)
Pset_QuantityTakeOff - Reference: 1500 mm x 900 mm
Name (Table et chaises - 2 élèves:1500 mm x 900 mm:...) | Material
1175623
1175624 | Peinture - Rouge, Plastique - Noir, Bois - Hêtre, Bois - Mélaminé beige
1175625 | Peinture - Rouge, Plastique - Noir, Bois - Hêtre, Bois - Mélaminé beige
1175626 | Peinture - Rouge, Plastique - Noir, Bois - Hêtre, Bois - Mélaminé beige
1175655 | Peinture - Rouge, Plastique - Noir, Bois - Hêtre, Bois - Mélaminé beige
1175662 | Peinture - Rouge, Plastique - Noir, Bois - Hêtre, Bois - Mélaminé beige
1175667 | Peinture - Rouge, Plastique - Noir, Bois - Hêtre, Bois - Mélaminé beige
1175672 | Peinture - Rouge, Plastique - Noir, Bois - Hêtre, Bois - Mélaminé beige
1175677 | Peinture - Rouge, Plastique - Noir, Bois - Hêtre, Bois - Mélaminé beige
1175682 | Peinture - Rouge, Plastique - Noir, Bois - Hêtre, Bois - Mélaminé beige

# IfcFurnishingElement: Table:800x650, Table:800x650:1175660
In: Niveau 1
Type - Material: Plastique - Noir (5), Peinture - Jaune, Bois - Mélaminé beige
Pset_QuantityTakeOff - Reference: 800x650

# IfcFurnishingElement: Tableau mural:1800 mm x 1000 mm - Luminaire (2)
In: Niveau 1
Type - Material: Métal - Aluminium (4), Tableau - Vert (3)
Pset_QuantityTakeOff - Reference: 1800 mm x 1000 mm - Luminaire
Name (Tableau mural:1800 mm x 1000 mm - Luminaire:...)
824013
824085 | Material: Métal - Aluminium, Tableau - Vert

# IfcOpeningElement: Opening (12)
Name | In
Mur de base:Générique - 140 mm:735242 | Niveau 1 | Pset_OpeningElementCommon - Reference: PP (1.16m x 2.04m); sets with these values: 2
Mur de base:Générique - 70 mm:736183 | Niveau 1 | Pset_OpeningElementCommon - Reference: 400x400; sets with these values: 2
Int. Simple:PP (0.83m x 2.04m):734273:1 | Niveau 0
Int. Double:PP (1.26m x 2.04m):734472:1 | Niveau 0
Int. Double:PP (1.46m x 2.04m):734534:1 | Niveau 0
Int. Double:PP (1.46m x 2.04m):734575:1 | Niveau 0
Int. Simple:PP (0.83m x 2.04m):735553:1 | Niveau 1
Int. Simple:PP (0.83m x 2.04m):735747:1 | Niveau 1
Int. Simple:PP (0.83m x 2.04m):810380:1 | Niveau 1
Int. Double:PP (1.16m x 2.04m):735926:1 | Niveau 1
Int. Simple:PP (0.83m x 2.04m):735665:1 | Niveau 1
Int. Simple:PP (0.83m x 2.04m):978431:1 | Niveau 1

# IfcPlate: Panneau système:Vitré (28)
Type - PredefinedType: CURTAIN_PANEL; Material: Verre
Type - Pset_PlateCommon - IsExternal: no
Pset_PlateCommon - Reference: Vitré
Pset_QuantityTakeOff - Reference: Vitré
Name (Panneau système:Vitré:...) | In
740003 | Niveau 0
740025 | Niveau 0
740027 | Niveau 0
740631 | Niveau 0
740633 | Niveau 0
740635 | Niveau 0
740655 | Niveau 0
740657 | Niveau 0
740659 | Niveau 0
740679 | Niveau 0
740681 | Niveau 0
740683 | Niveau 0
740855 | Niveau 0
740860 | Niveau 0
741320 | Niveau 1
741323 | Niveau 1
741325 | Niveau 1
741388 | Niveau 1
741390 | Niveau 1
741392 | Niveau 1
741412 | Niveau 1
741414 | Niveau 1
741416 | Niveau 1
741436 | Niveau 1
741438 | Niveau 1
741440 | Niveau 1
741661 | Niveau 1
741664 | Niveau 1

# IfcRoof: Toit de base:Générique - 300 mm, Toit de base:Générique - 300 mm:1194896
In: Niveau 2
Material: Acier 300 mm
Pset_QuantityTakeOff - Reference: Générique - 300 mm
Pset_RoofCommon - IsExternal: yes; Reference: Générique - 300 mm; ProjectedArea: 201.512 m2; TotalArea: 202.69 m2

# IfcSlab: Sol:Générique 260 mm, Sol:Générique 260 mm:736213
In: Niveau 1
Type - PredefinedType: FLOOR; Material: Sol par défaut 260 mm
Type - Pset_SlabCommon - IsExternal: no
Pset_QuantityTakeOff - Reference: Générique 260 mm; sets with these values: 2
Pset_SlabCommon - LoadBearing: no; PitchAngle: 0 deg; Reference: Générique 260 mm

# IfcSlab: Sol:Générique 270 mm, Sol:Générique 270 mm:734709
In: Niveau 0
Type - PredefinedType: FLOOR; Material: Sol par défaut 270 mm
Type - Pset_SlabCommon - IsExternal: no
Pset_QuantityTakeOff - Reference: Générique 270 mm; sets with these values: 2
Pset_SlabCommon - LoadBearing: no; Reference: Générique 270 mm; PitchAngle: 0 deg

# IfcWall: Mur de base:Générique - 140 mm (3)
In: Niveau 1
Type - PredefinedType: STANDARD; Material: Peinture 140 mm
Type - Pset_WallCommon - IsExternal: yes
Pset_QuantityTakeOff - Reference: Générique - 140 mm; sets with these values: 2
Pset_WallCommon - ExtendToStructure: yes; LoadBearing: no; Reference: Générique - 140 mm
Name (Mur de base:Générique - 140 mm:...)
734936
735078
735345

# IfcWall: Mur de base:Générique - 320 mm (4)
In: Niveau 0
Type - PredefinedType: STANDARD; Material: Plaque de mur de gypse 320 mm
Type - Pset_WallCommon - ThermalTransmittance: 2.03125 kg/K/s3; IsExternal: yes
Pset_QuantityTakeOff - Reference: Générique - 320 mm; sets with these values: 2
Pset_WallCommon - Reference: Générique - 320 mm; ExtendToStructure: yes; LoadBearing: no
Name (Mur de base:Générique - 320 mm:...)
726441
726735
726800
726865

# IfcWallStandardCase: Mur de base:Générique - 100 mm (2)
In: Niveau 0
Type - PredefinedType: STANDARD; Material: Peinture 100 mm
Type - Pset_WallCommon - IsExternal: yes
Pset_QuantityTakeOff - Reference: Générique - 100 mm; sets with these values: 2
Pset_WallCommon - ExtendToStructure: yes; LoadBearing: no; Reference: Générique - 100 mm
Name (Mur de base:Générique - 100 mm:...)
727400
727426

# IfcWallStandardCase: Mur de base:Générique - 140 mm (11)
Type - PredefinedType: STANDARD; Material: Peinture 140 mm
Type - Pset_WallCommon - IsExternal: yes
Pset_QuantityTakeOff - Reference: Générique - 140 mm; sets with these values: 2
Pset_WallCommon - LoadBearing: no; Reference: Générique - 140 mm
Name (Mur de base:Générique - 140 mm:...) | In | ExtendToStructure
727013 | Niveau 0 | yes
727049 | Niveau 0 | yes
727131 | Niveau 0 | yes
727176 | Niveau 0 | yes
727273 | Niveau 0 | yes
727310 | Niveau 0 | yes
735242 | Niveau 1 | no
735295 | Niveau 1 | no
735410 | Niveau 1 | no
735437 | Niveau 1 | no
735470 | Niveau 1 | no

# IfcWallStandardCase: Mur de base:Générique - 180 mm, Mur de base:Générique - 180 mm:735004
In: Niveau 1
Type - PredefinedType: STANDARD; Material: Mur par défaut 180 mm
Type - Pset_WallCommon - IsExternal: yes
Pset_QuantityTakeOff - Reference: Générique - 180 mm; sets with these values: 2
Pset_WallCommon - LoadBearing: no; Reference: Générique - 180 mm; ExtendToStructure: no

# IfcWallStandardCase: Mur de base:Générique - 70 mm (2)
In: Niveau 1
Type - PredefinedType: STANDARD; Material: Peinture 70 mm
Type - Pset_WallCommon - IsExternal: yes
Pset_QuantityTakeOff - Reference: Générique - 70 mm; sets with these values: 2
Pset_WallCommon - LoadBearing: no; ExtendToStructure: no; Reference: Générique - 70 mm
Name (Mur de base:Générique - 70 mm:...)
736141
736183
